VERSION 5.8 ;
BUSBITCHARS "[]" ;
DIVIDERCHAR "/" ;
UNITS
    DATABASE MICRONS 1000 ;
END UNITS

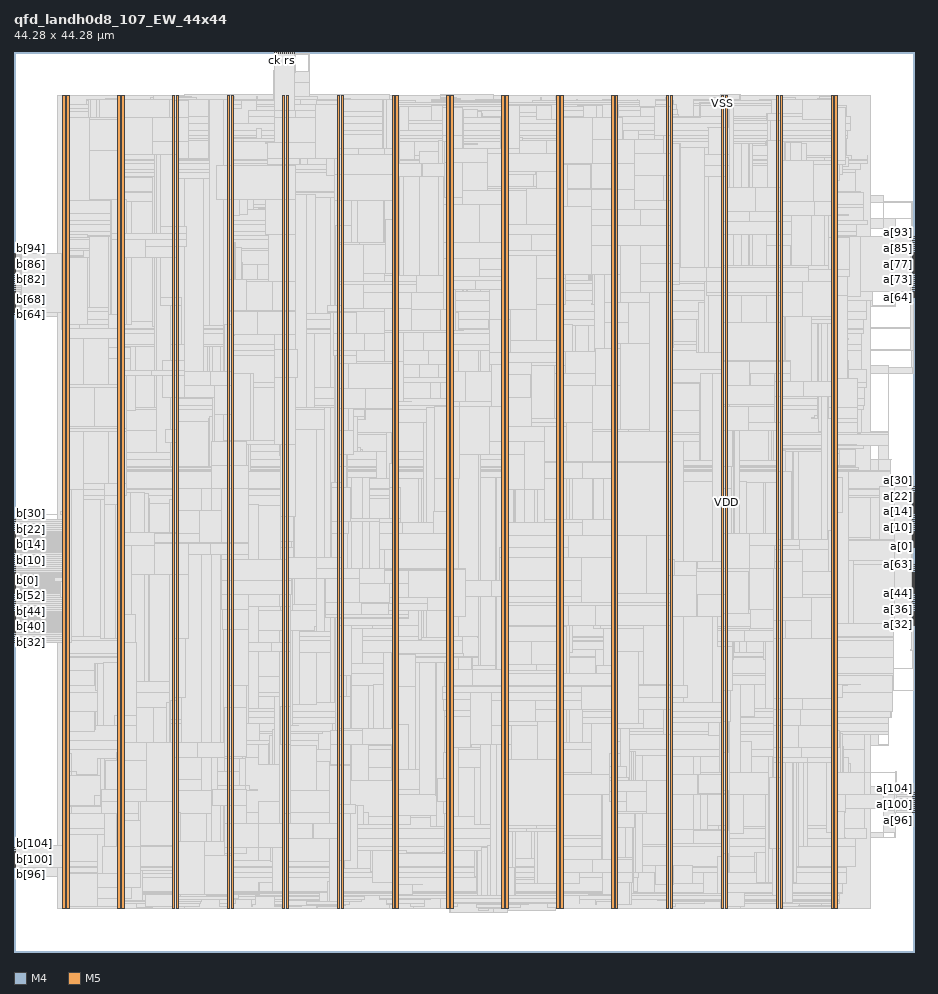
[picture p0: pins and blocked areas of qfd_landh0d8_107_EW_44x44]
MACRO qfd_landh0d8_107_EW_44x44
  FOREIGN qfd_landh0d8_107_EW_44x44 0 0 ;
  CLASS BLOCK ;
  SIZE 44.28 BY 44.28 ;
  PIN a[0]
    DIRECTION INPUT ;
    USE SIGNAL ;
    PORT
      LAYER M4 ;
        RECT  44.196 19.92 44.28 19.944 ;
    END
  END a[0]
  PIN a[100]
    DIRECTION INPUT ;
    USE SIGNAL ;
    PORT
      LAYER M4 ;
        RECT  44.196 7.248 44.28 7.272 ;
    END
  END a[100]
  PIN a[101]
    DIRECTION INPUT ;
    USE SIGNAL ;
    PORT
      LAYER M4 ;
        RECT  44.196 7.344 44.28 7.368 ;
    END
  END a[101]
  PIN a[102]
    DIRECTION INPUT ;
    USE SIGNAL ;
    PORT
      LAYER M4 ;
        RECT  44.196 7.44 44.28 7.464 ;
    END
  END a[102]
  PIN a[103]
    DIRECTION INPUT ;
    USE SIGNAL ;
    PORT
      LAYER M4 ;
        RECT  44.196 7.536 44.28 7.56 ;
    END
  END a[103]
  PIN a[104]
    DIRECTION INPUT ;
    USE SIGNAL ;
    PORT
      LAYER M4 ;
        RECT  44.196 7.632 44.28 7.656 ;
    END
  END a[104]
  PIN a[105]
    DIRECTION INPUT ;
    USE SIGNAL ;
    PORT
      LAYER M4 ;
        RECT  44.196 7.728 44.28 7.752 ;
    END
  END a[105]
  PIN a[106]
    DIRECTION INPUT ;
    USE SIGNAL ;
    PORT
      LAYER M4 ;
        RECT  44.196 7.824 44.28 7.848 ;
    END
  END a[106]
  PIN a[10]
    DIRECTION INPUT ;
    USE SIGNAL ;
    PORT
      LAYER M4 ;
        RECT  44.196 20.88 44.28 20.904 ;
    END
  END a[10]
  PIN a[11]
    DIRECTION INPUT ;
    USE SIGNAL ;
    PORT
      LAYER M4 ;
        RECT  44.196 20.976 44.28 21 ;
    END
  END a[11]
  PIN a[12]
    DIRECTION INPUT ;
    USE SIGNAL ;
    PORT
      LAYER M4 ;
        RECT  44.196 21.072 44.28 21.096 ;
    END
  END a[12]
  PIN a[13]
    DIRECTION INPUT ;
    USE SIGNAL ;
    PORT
      LAYER M4 ;
        RECT  44.196 21.168 44.28 21.192 ;
    END
  END a[13]
  PIN a[14]
    DIRECTION INPUT ;
    USE SIGNAL ;
    PORT
      LAYER M4 ;
        RECT  44.196 21.264 44.28 21.288 ;
    END
  END a[14]
  PIN a[15]
    DIRECTION INPUT ;
    USE SIGNAL ;
    PORT
      LAYER M4 ;
        RECT  44.196 21.36 44.28 21.384 ;
    END
  END a[15]
  PIN a[16]
    DIRECTION INPUT ;
    USE SIGNAL ;
    PORT
      LAYER M4 ;
        RECT  44.196 21.456 44.28 21.48 ;
    END
  END a[16]
  PIN a[17]
    DIRECTION INPUT ;
    USE SIGNAL ;
    PORT
      LAYER M4 ;
        RECT  44.196 21.552 44.28 21.576 ;
    END
  END a[17]
  PIN a[18]
    DIRECTION INPUT ;
    USE SIGNAL ;
    PORT
      LAYER M4 ;
        RECT  44.196 21.648 44.28 21.672 ;
    END
  END a[18]
  PIN a[19]
    DIRECTION INPUT ;
    USE SIGNAL ;
    PORT
      LAYER M4 ;
        RECT  44.196 21.744 44.28 21.768 ;
    END
  END a[19]
  PIN a[1]
    DIRECTION INPUT ;
    USE SIGNAL ;
    PORT
      LAYER M4 ;
        RECT  44.196 20.016 44.28 20.04 ;
    END
  END a[1]
  PIN a[20]
    DIRECTION INPUT ;
    USE SIGNAL ;
    PORT
      LAYER M4 ;
        RECT  44.196 21.84 44.28 21.864 ;
    END
  END a[20]
  PIN a[21]
    DIRECTION INPUT ;
    USE SIGNAL ;
    PORT
      LAYER M4 ;
        RECT  44.196 21.936 44.28 21.96 ;
    END
  END a[21]
  PIN a[22]
    DIRECTION INPUT ;
    USE SIGNAL ;
    PORT
      LAYER M4 ;
        RECT  44.196 22.032 44.28 22.056 ;
    END
  END a[22]
  PIN a[23]
    DIRECTION INPUT ;
    USE SIGNAL ;
    PORT
      LAYER M4 ;
        RECT  44.196 22.128 44.28 22.152 ;
    END
  END a[23]
  PIN a[24]
    DIRECTION INPUT ;
    USE SIGNAL ;
    PORT
      LAYER M4 ;
        RECT  44.196 22.224 44.28 22.248 ;
    END
  END a[24]
  PIN a[25]
    DIRECTION INPUT ;
    USE SIGNAL ;
    PORT
      LAYER M4 ;
        RECT  44.196 22.32 44.28 22.344 ;
    END
  END a[25]
  PIN a[26]
    DIRECTION INPUT ;
    USE SIGNAL ;
    PORT
      LAYER M4 ;
        RECT  44.196 22.416 44.28 22.44 ;
    END
  END a[26]
  PIN a[27]
    DIRECTION INPUT ;
    USE SIGNAL ;
    PORT
      LAYER M4 ;
        RECT  44.196 22.512 44.28 22.536 ;
    END
  END a[27]
  PIN a[28]
    DIRECTION INPUT ;
    USE SIGNAL ;
    PORT
      LAYER M4 ;
        RECT  44.196 22.608 44.28 22.632 ;
    END
  END a[28]
  PIN a[29]
    DIRECTION INPUT ;
    USE SIGNAL ;
    PORT
      LAYER M4 ;
        RECT  44.196 22.704 44.28 22.728 ;
    END
  END a[29]
  PIN a[2]
    DIRECTION INPUT ;
    USE SIGNAL ;
    PORT
      LAYER M4 ;
        RECT  44.196 20.112 44.28 20.136 ;
    END
  END a[2]
  PIN a[30]
    DIRECTION INPUT ;
    USE SIGNAL ;
    PORT
      LAYER M4 ;
        RECT  44.196 22.8 44.28 22.824 ;
    END
  END a[30]
  PIN a[31]
    DIRECTION INPUT ;
    USE SIGNAL ;
    PORT
      LAYER M4 ;
        RECT  44.196 22.896 44.28 22.92 ;
    END
  END a[31]
  PIN a[32]
    DIRECTION INPUT ;
    USE SIGNAL ;
    PORT
      LAYER M4 ;
        RECT  44.196 16.08 44.28 16.104 ;
    END
  END a[32]
  PIN a[33]
    DIRECTION INPUT ;
    USE SIGNAL ;
    PORT
      LAYER M4 ;
        RECT  44.196 16.176 44.28 16.2 ;
    END
  END a[33]
  PIN a[34]
    DIRECTION INPUT ;
    USE SIGNAL ;
    PORT
      LAYER M4 ;
        RECT  44.196 16.272 44.28 16.296 ;
    END
  END a[34]
  PIN a[35]
    DIRECTION INPUT ;
    USE SIGNAL ;
    PORT
      LAYER M4 ;
        RECT  44.196 16.368 44.28 16.392 ;
    END
  END a[35]
  PIN a[36]
    DIRECTION INPUT ;
    USE SIGNAL ;
    PORT
      LAYER M4 ;
        RECT  44.196 16.464 44.28 16.488 ;
    END
  END a[36]
  PIN a[37]
    DIRECTION INPUT ;
    USE SIGNAL ;
    PORT
      LAYER M4 ;
        RECT  44.196 16.56 44.28 16.584 ;
    END
  END a[37]
  PIN a[38]
    DIRECTION INPUT ;
    USE SIGNAL ;
    PORT
      LAYER M4 ;
        RECT  44.196 16.656 44.28 16.68 ;
    END
  END a[38]
  PIN a[39]
    DIRECTION INPUT ;
    USE SIGNAL ;
    PORT
      LAYER M4 ;
        RECT  44.196 16.752 44.28 16.776 ;
    END
  END a[39]
  PIN a[3]
    DIRECTION INPUT ;
    USE SIGNAL ;
    PORT
      LAYER M4 ;
        RECT  44.196 20.208 44.28 20.232 ;
    END
  END a[3]
  PIN a[40]
    DIRECTION INPUT ;
    USE SIGNAL ;
    PORT
      LAYER M4 ;
        RECT  44.196 16.848 44.28 16.872 ;
    END
  END a[40]
  PIN a[41]
    DIRECTION INPUT ;
    USE SIGNAL ;
    PORT
      LAYER M4 ;
        RECT  44.196 16.944 44.28 16.968 ;
    END
  END a[41]
  PIN a[42]
    DIRECTION INPUT ;
    USE SIGNAL ;
    PORT
      LAYER M4 ;
        RECT  44.196 17.04 44.28 17.064 ;
    END
  END a[42]
  PIN a[43]
    DIRECTION INPUT ;
    USE SIGNAL ;
    PORT
      LAYER M4 ;
        RECT  44.196 17.136 44.28 17.16 ;
    END
  END a[43]
  PIN a[44]
    DIRECTION INPUT ;
    USE SIGNAL ;
    PORT
      LAYER M4 ;
        RECT  44.196 17.232 44.28 17.256 ;
    END
  END a[44]
  PIN a[45]
    DIRECTION INPUT ;
    USE SIGNAL ;
    PORT
      LAYER M4 ;
        RECT  44.196 17.328 44.28 17.352 ;
    END
  END a[45]
  PIN a[46]
    DIRECTION INPUT ;
    USE SIGNAL ;
    PORT
      LAYER M4 ;
        RECT  44.196 17.424 44.28 17.448 ;
    END
  END a[46]
  PIN a[47]
    DIRECTION INPUT ;
    USE SIGNAL ;
    PORT
      LAYER M4 ;
        RECT  44.196 17.52 44.28 17.544 ;
    END
  END a[47]
  PIN a[48]
    DIRECTION INPUT ;
    USE SIGNAL ;
    PORT
      LAYER M4 ;
        RECT  44.196 17.616 44.28 17.64 ;
    END
  END a[48]
  PIN a[49]
    DIRECTION INPUT ;
    USE SIGNAL ;
    PORT
      LAYER M4 ;
        RECT  44.196 17.712 44.28 17.736 ;
    END
  END a[49]
  PIN a[4]
    DIRECTION INPUT ;
    USE SIGNAL ;
    PORT
      LAYER M4 ;
        RECT  44.196 20.304 44.28 20.328 ;
    END
  END a[4]
  PIN a[50]
    DIRECTION INPUT ;
    USE SIGNAL ;
    PORT
      LAYER M4 ;
        RECT  44.196 17.808 44.28 17.832 ;
    END
  END a[50]
  PIN a[51]
    DIRECTION INPUT ;
    USE SIGNAL ;
    PORT
      LAYER M4 ;
        RECT  44.196 17.904 44.28 17.928 ;
    END
  END a[51]
  PIN a[52]
    DIRECTION INPUT ;
    USE SIGNAL ;
    PORT
      LAYER M4 ;
        RECT  44.196 18 44.28 18.024 ;
    END
  END a[52]
  PIN a[53]
    DIRECTION INPUT ;
    USE SIGNAL ;
    PORT
      LAYER M4 ;
        RECT  44.196 18.096 44.28 18.12 ;
    END
  END a[53]
  PIN a[54]
    DIRECTION INPUT ;
    USE SIGNAL ;
    PORT
      LAYER M4 ;
        RECT  44.196 18.192 44.28 18.216 ;
    END
  END a[54]
  PIN a[55]
    DIRECTION INPUT ;
    USE SIGNAL ;
    PORT
      LAYER M4 ;
        RECT  44.196 18.288 44.28 18.312 ;
    END
  END a[55]
  PIN a[56]
    DIRECTION INPUT ;
    USE SIGNAL ;
    PORT
      LAYER M4 ;
        RECT  44.196 18.384 44.28 18.408 ;
    END
  END a[56]
  PIN a[57]
    DIRECTION INPUT ;
    USE SIGNAL ;
    PORT
      LAYER M4 ;
        RECT  44.196 18.48 44.28 18.504 ;
    END
  END a[57]
  PIN a[58]
    DIRECTION INPUT ;
    USE SIGNAL ;
    PORT
      LAYER M4 ;
        RECT  44.196 18.576 44.28 18.6 ;
    END
  END a[58]
  PIN a[59]
    DIRECTION INPUT ;
    USE SIGNAL ;
    PORT
      LAYER M4 ;
        RECT  44.196 18.672 44.28 18.696 ;
    END
  END a[59]
  PIN a[5]
    DIRECTION INPUT ;
    USE SIGNAL ;
    PORT
      LAYER M4 ;
        RECT  44.196 20.4 44.28 20.424 ;
    END
  END a[5]
  PIN a[60]
    DIRECTION INPUT ;
    USE SIGNAL ;
    PORT
      LAYER M4 ;
        RECT  44.196 18.768 44.28 18.792 ;
    END
  END a[60]
  PIN a[61]
    DIRECTION INPUT ;
    USE SIGNAL ;
    PORT
      LAYER M4 ;
        RECT  44.196 18.864 44.28 18.888 ;
    END
  END a[61]
  PIN a[62]
    DIRECTION INPUT ;
    USE SIGNAL ;
    PORT
      LAYER M4 ;
        RECT  44.196 18.96 44.28 18.984 ;
    END
  END a[62]
  PIN a[63]
    DIRECTION INPUT ;
    USE SIGNAL ;
    PORT
      LAYER M4 ;
        RECT  44.196 19.056 44.28 19.08 ;
    END
  END a[63]
  PIN a[64]
    DIRECTION INPUT ;
    USE SIGNAL ;
    PORT
      LAYER M4 ;
        RECT  44.196 32.208 44.28 32.232 ;
    END
  END a[64]
  PIN a[65]
    DIRECTION INPUT ;
    USE SIGNAL ;
    PORT
      LAYER M4 ;
        RECT  44.196 32.304 44.28 32.328 ;
    END
  END a[65]
  PIN a[66]
    DIRECTION INPUT ;
    USE SIGNAL ;
    PORT
      LAYER M4 ;
        RECT  44.196 32.4 44.28 32.424 ;
    END
  END a[66]
  PIN a[67]
    DIRECTION INPUT ;
    USE SIGNAL ;
    PORT
      LAYER M4 ;
        RECT  44.196 32.496 44.28 32.52 ;
    END
  END a[67]
  PIN a[68]
    DIRECTION INPUT ;
    USE SIGNAL ;
    PORT
      LAYER M4 ;
        RECT  44.196 32.592 44.28 32.616 ;
    END
  END a[68]
  PIN a[69]
    DIRECTION INPUT ;
    USE SIGNAL ;
    PORT
      LAYER M4 ;
        RECT  44.196 32.688 44.28 32.712 ;
    END
  END a[69]
  PIN a[6]
    DIRECTION INPUT ;
    USE SIGNAL ;
    PORT
      LAYER M4 ;
        RECT  44.196 20.496 44.28 20.52 ;
    END
  END a[6]
  PIN a[70]
    DIRECTION INPUT ;
    USE SIGNAL ;
    PORT
      LAYER M4 ;
        RECT  44.196 32.784 44.28 32.808 ;
    END
  END a[70]
  PIN a[71]
    DIRECTION INPUT ;
    USE SIGNAL ;
    PORT
      LAYER M4 ;
        RECT  44.196 32.88 44.28 32.904 ;
    END
  END a[71]
  PIN a[72]
    DIRECTION INPUT ;
    USE SIGNAL ;
    PORT
      LAYER M4 ;
        RECT  44.196 32.976 44.28 33 ;
    END
  END a[72]
  PIN a[73]
    DIRECTION INPUT ;
    USE SIGNAL ;
    PORT
      LAYER M4 ;
        RECT  44.196 33.072 44.28 33.096 ;
    END
  END a[73]
  PIN a[74]
    DIRECTION INPUT ;
    USE SIGNAL ;
    PORT
      LAYER M4 ;
        RECT  44.196 33.168 44.28 33.192 ;
    END
  END a[74]
  PIN a[75]
    DIRECTION INPUT ;
    USE SIGNAL ;
    PORT
      LAYER M4 ;
        RECT  44.196 33.264 44.28 33.288 ;
    END
  END a[75]
  PIN a[76]
    DIRECTION INPUT ;
    USE SIGNAL ;
    PORT
      LAYER M4 ;
        RECT  44.196 33.36 44.28 33.384 ;
    END
  END a[76]
  PIN a[77]
    DIRECTION INPUT ;
    USE SIGNAL ;
    PORT
      LAYER M4 ;
        RECT  44.196 33.456 44.28 33.48 ;
    END
  END a[77]
  PIN a[78]
    DIRECTION INPUT ;
    USE SIGNAL ;
    PORT
      LAYER M4 ;
        RECT  44.196 33.552 44.28 33.576 ;
    END
  END a[78]
  PIN a[79]
    DIRECTION INPUT ;
    USE SIGNAL ;
    PORT
      LAYER M4 ;
        RECT  44.196 33.648 44.28 33.672 ;
    END
  END a[79]
  PIN a[7]
    DIRECTION INPUT ;
    USE SIGNAL ;
    PORT
      LAYER M4 ;
        RECT  44.196 20.592 44.28 20.616 ;
    END
  END a[7]
  PIN a[80]
    DIRECTION INPUT ;
    USE SIGNAL ;
    PORT
      LAYER M4 ;
        RECT  44.196 33.744 44.28 33.768 ;
    END
  END a[80]
  PIN a[81]
    DIRECTION INPUT ;
    USE SIGNAL ;
    PORT
      LAYER M4 ;
        RECT  44.196 33.84 44.28 33.864 ;
    END
  END a[81]
  PIN a[82]
    DIRECTION INPUT ;
    USE SIGNAL ;
    PORT
      LAYER M4 ;
        RECT  44.196 33.936 44.28 33.96 ;
    END
  END a[82]
  PIN a[83]
    DIRECTION INPUT ;
    USE SIGNAL ;
    PORT
      LAYER M4 ;
        RECT  44.196 34.032 44.28 34.056 ;
    END
  END a[83]
  PIN a[84]
    DIRECTION INPUT ;
    USE SIGNAL ;
    PORT
      LAYER M4 ;
        RECT  44.196 34.128 44.28 34.152 ;
    END
  END a[84]
  PIN a[85]
    DIRECTION INPUT ;
    USE SIGNAL ;
    PORT
      LAYER M4 ;
        RECT  44.196 34.224 44.28 34.248 ;
    END
  END a[85]
  PIN a[86]
    DIRECTION INPUT ;
    USE SIGNAL ;
    PORT
      LAYER M4 ;
        RECT  44.196 34.32 44.28 34.344 ;
    END
  END a[86]
  PIN a[87]
    DIRECTION INPUT ;
    USE SIGNAL ;
    PORT
      LAYER M4 ;
        RECT  44.196 34.416 44.28 34.44 ;
    END
  END a[87]
  PIN a[88]
    DIRECTION INPUT ;
    USE SIGNAL ;
    PORT
      LAYER M4 ;
        RECT  44.196 34.512 44.28 34.536 ;
    END
  END a[88]
  PIN a[89]
    DIRECTION INPUT ;
    USE SIGNAL ;
    PORT
      LAYER M4 ;
        RECT  44.196 34.608 44.28 34.632 ;
    END
  END a[89]
  PIN a[8]
    DIRECTION INPUT ;
    USE SIGNAL ;
    PORT
      LAYER M4 ;
        RECT  44.196 20.688 44.28 20.712 ;
    END
  END a[8]
  PIN a[90]
    DIRECTION INPUT ;
    USE SIGNAL ;
    PORT
      LAYER M4 ;
        RECT  44.196 34.704 44.28 34.728 ;
    END
  END a[90]
  PIN a[91]
    DIRECTION INPUT ;
    USE SIGNAL ;
    PORT
      LAYER M4 ;
        RECT  44.196 34.8 44.28 34.824 ;
    END
  END a[91]
  PIN a[92]
    DIRECTION INPUT ;
    USE SIGNAL ;
    PORT
      LAYER M4 ;
        RECT  44.196 34.896 44.28 34.92 ;
    END
  END a[92]
  PIN a[93]
    DIRECTION INPUT ;
    USE SIGNAL ;
    PORT
      LAYER M4 ;
        RECT  44.196 34.992 44.28 35.016 ;
    END
  END a[93]
  PIN a[94]
    DIRECTION INPUT ;
    USE SIGNAL ;
    PORT
      LAYER M4 ;
        RECT  44.196 35.088 44.28 35.112 ;
    END
  END a[94]
  PIN a[95]
    DIRECTION INPUT ;
    USE SIGNAL ;
    PORT
      LAYER M4 ;
        RECT  44.196 35.184 44.28 35.208 ;
    END
  END a[95]
  PIN a[96]
    DIRECTION INPUT ;
    USE SIGNAL ;
    PORT
      LAYER M4 ;
        RECT  44.196 6.864 44.28 6.888 ;
    END
  END a[96]
  PIN a[97]
    DIRECTION INPUT ;
    USE SIGNAL ;
    PORT
      LAYER M4 ;
        RECT  44.196 6.96 44.28 6.984 ;
    END
  END a[97]
  PIN a[98]
    DIRECTION INPUT ;
    USE SIGNAL ;
    PORT
      LAYER M4 ;
        RECT  44.196 7.056 44.28 7.08 ;
    END
  END a[98]
  PIN a[99]
    DIRECTION INPUT ;
    USE SIGNAL ;
    PORT
      LAYER M4 ;
        RECT  44.196 7.152 44.28 7.176 ;
    END
  END a[99]
  PIN a[9]
    DIRECTION INPUT ;
    USE SIGNAL ;
    PORT
      LAYER M4 ;
        RECT  44.196 20.784 44.28 20.808 ;
    END
  END a[9]
  PIN b[0]
    DIRECTION OUTPUT ;
    USE SIGNAL ;
    PORT
      LAYER M4 ;
        RECT  0 18.288 0.084 18.312 ;
    END
  END b[0]
  PIN b[100]
    DIRECTION OUTPUT ;
    USE SIGNAL ;
    PORT
      LAYER M4 ;
        RECT  0 4.56 0.084 4.584 ;
    END
  END b[100]
  PIN b[101]
    DIRECTION OUTPUT ;
    USE SIGNAL ;
    PORT
      LAYER M4 ;
        RECT  0 4.656 0.084 4.68 ;
    END
  END b[101]
  PIN b[102]
    DIRECTION OUTPUT ;
    USE SIGNAL ;
    PORT
      LAYER M4 ;
        RECT  0 4.752 0.084 4.776 ;
    END
  END b[102]
  PIN b[103]
    DIRECTION OUTPUT ;
    USE SIGNAL ;
    PORT
      LAYER M4 ;
        RECT  0 4.848 0.084 4.872 ;
    END
  END b[103]
  PIN b[104]
    DIRECTION OUTPUT ;
    USE SIGNAL ;
    PORT
      LAYER M4 ;
        RECT  0 4.944 0.084 4.968 ;
    END
  END b[104]
  PIN b[105]
    DIRECTION OUTPUT ;
    USE SIGNAL ;
    PORT
      LAYER M4 ;
        RECT  0 5.04 0.084 5.064 ;
    END
  END b[105]
  PIN b[106]
    DIRECTION OUTPUT ;
    USE SIGNAL ;
    PORT
      LAYER M4 ;
        RECT  0 5.136 0.084 5.16 ;
    END
  END b[106]
  PIN b[10]
    DIRECTION OUTPUT ;
    USE SIGNAL ;
    PORT
      LAYER M4 ;
        RECT  0 19.248 0.084 19.272 ;
    END
  END b[10]
  PIN b[11]
    DIRECTION OUTPUT ;
    USE SIGNAL ;
    PORT
      LAYER M4 ;
        RECT  0 19.344 0.084 19.368 ;
    END
  END b[11]
  PIN b[12]
    DIRECTION OUTPUT ;
    USE SIGNAL ;
    PORT
      LAYER M4 ;
        RECT  0 19.44 0.084 19.464 ;
    END
  END b[12]
  PIN b[13]
    DIRECTION OUTPUT ;
    USE SIGNAL ;
    PORT
      LAYER M4 ;
        RECT  0 19.536 0.084 19.56 ;
    END
  END b[13]
  PIN b[14]
    DIRECTION OUTPUT ;
    USE SIGNAL ;
    PORT
      LAYER M4 ;
        RECT  0 19.632 0.084 19.656 ;
    END
  END b[14]
  PIN b[15]
    DIRECTION OUTPUT ;
    USE SIGNAL ;
    PORT
      LAYER M4 ;
        RECT  0 19.728 0.084 19.752 ;
    END
  END b[15]
  PIN b[16]
    DIRECTION OUTPUT ;
    USE SIGNAL ;
    PORT
      LAYER M4 ;
        RECT  0 19.824 0.084 19.848 ;
    END
  END b[16]
  PIN b[17]
    DIRECTION OUTPUT ;
    USE SIGNAL ;
    PORT
      LAYER M4 ;
        RECT  0 19.92 0.084 19.944 ;
    END
  END b[17]
  PIN b[18]
    DIRECTION OUTPUT ;
    USE SIGNAL ;
    PORT
      LAYER M4 ;
        RECT  0 20.016 0.084 20.04 ;
    END
  END b[18]
  PIN b[19]
    DIRECTION OUTPUT ;
    USE SIGNAL ;
    PORT
      LAYER M4 ;
        RECT  0 20.112 0.084 20.136 ;
    END
  END b[19]
  PIN b[1]
    DIRECTION OUTPUT ;
    USE SIGNAL ;
    PORT
      LAYER M4 ;
        RECT  0 18.384 0.084 18.408 ;
    END
  END b[1]
  PIN b[20]
    DIRECTION OUTPUT ;
    USE SIGNAL ;
    PORT
      LAYER M4 ;
        RECT  0 20.208 0.084 20.232 ;
    END
  END b[20]
  PIN b[21]
    DIRECTION OUTPUT ;
    USE SIGNAL ;
    PORT
      LAYER M4 ;
        RECT  0 20.304 0.084 20.328 ;
    END
  END b[21]
  PIN b[22]
    DIRECTION OUTPUT ;
    USE SIGNAL ;
    PORT
      LAYER M4 ;
        RECT  0 20.4 0.084 20.424 ;
    END
  END b[22]
  PIN b[23]
    DIRECTION OUTPUT ;
    USE SIGNAL ;
    PORT
      LAYER M4 ;
        RECT  0 20.496 0.084 20.52 ;
    END
  END b[23]
  PIN b[24]
    DIRECTION OUTPUT ;
    USE SIGNAL ;
    PORT
      LAYER M4 ;
        RECT  0 20.592 0.084 20.616 ;
    END
  END b[24]
  PIN b[25]
    DIRECTION OUTPUT ;
    USE SIGNAL ;
    PORT
      LAYER M4 ;
        RECT  0 20.688 0.084 20.712 ;
    END
  END b[25]
  PIN b[26]
    DIRECTION OUTPUT ;
    USE SIGNAL ;
    PORT
      LAYER M4 ;
        RECT  0 20.784 0.084 20.808 ;
    END
  END b[26]
  PIN b[27]
    DIRECTION OUTPUT ;
    USE SIGNAL ;
    PORT
      LAYER M4 ;
        RECT  0 20.88 0.084 20.904 ;
    END
  END b[27]
  PIN b[28]
    DIRECTION OUTPUT ;
    USE SIGNAL ;
    PORT
      LAYER M4 ;
        RECT  0 20.976 0.084 21 ;
    END
  END b[28]
  PIN b[29]
    DIRECTION OUTPUT ;
    USE SIGNAL ;
    PORT
      LAYER M4 ;
        RECT  0 21.072 0.084 21.096 ;
    END
  END b[29]
  PIN b[2]
    DIRECTION OUTPUT ;
    USE SIGNAL ;
    PORT
      LAYER M4 ;
        RECT  0 18.48 0.084 18.504 ;
    END
  END b[2]
  PIN b[30]
    DIRECTION OUTPUT ;
    USE SIGNAL ;
    PORT
      LAYER M4 ;
        RECT  0 21.168 0.084 21.192 ;
    END
  END b[30]
  PIN b[31]
    DIRECTION OUTPUT ;
    USE SIGNAL ;
    PORT
      LAYER M4 ;
        RECT  0 21.264 0.084 21.288 ;
    END
  END b[31]
  PIN b[32]
    DIRECTION OUTPUT ;
    USE SIGNAL ;
    PORT
      LAYER M4 ;
        RECT  0 15.216 0.084 15.24 ;
    END
  END b[32]
  PIN b[33]
    DIRECTION OUTPUT ;
    USE SIGNAL ;
    PORT
      LAYER M4 ;
        RECT  0 15.312 0.084 15.336 ;
    END
  END b[33]
  PIN b[34]
    DIRECTION OUTPUT ;
    USE SIGNAL ;
    PORT
      LAYER M4 ;
        RECT  0 15.408 0.084 15.432 ;
    END
  END b[34]
  PIN b[35]
    DIRECTION OUTPUT ;
    USE SIGNAL ;
    PORT
      LAYER M4 ;
        RECT  0 15.504 0.084 15.528 ;
    END
  END b[35]
  PIN b[36]
    DIRECTION OUTPUT ;
    USE SIGNAL ;
    PORT
      LAYER M4 ;
        RECT  0 15.6 0.084 15.624 ;
    END
  END b[36]
  PIN b[37]
    DIRECTION OUTPUT ;
    USE SIGNAL ;
    PORT
      LAYER M4 ;
        RECT  0 15.696 0.084 15.72 ;
    END
  END b[37]
  PIN b[38]
    DIRECTION OUTPUT ;
    USE SIGNAL ;
    PORT
      LAYER M4 ;
        RECT  0 15.792 0.084 15.816 ;
    END
  END b[38]
  PIN b[39]
    DIRECTION OUTPUT ;
    USE SIGNAL ;
    PORT
      LAYER M4 ;
        RECT  0 15.888 0.084 15.912 ;
    END
  END b[39]
  PIN b[3]
    DIRECTION OUTPUT ;
    USE SIGNAL ;
    PORT
      LAYER M4 ;
        RECT  0 18.576 0.084 18.6 ;
    END
  END b[3]
  PIN b[40]
    DIRECTION OUTPUT ;
    USE SIGNAL ;
    PORT
      LAYER M4 ;
        RECT  0 15.984 0.084 16.008 ;
    END
  END b[40]
  PIN b[41]
    DIRECTION OUTPUT ;
    USE SIGNAL ;
    PORT
      LAYER M4 ;
        RECT  0 16.08 0.084 16.104 ;
    END
  END b[41]
  PIN b[42]
    DIRECTION OUTPUT ;
    USE SIGNAL ;
    PORT
      LAYER M4 ;
        RECT  0 16.176 0.084 16.2 ;
    END
  END b[42]
  PIN b[43]
    DIRECTION OUTPUT ;
    USE SIGNAL ;
    PORT
      LAYER M4 ;
        RECT  0 16.272 0.084 16.296 ;
    END
  END b[43]
  PIN b[44]
    DIRECTION OUTPUT ;
    USE SIGNAL ;
    PORT
      LAYER M4 ;
        RECT  0 16.368 0.084 16.392 ;
    END
  END b[44]
  PIN b[45]
    DIRECTION OUTPUT ;
    USE SIGNAL ;
    PORT
      LAYER M4 ;
        RECT  0 16.464 0.084 16.488 ;
    END
  END b[45]
  PIN b[46]
    DIRECTION OUTPUT ;
    USE SIGNAL ;
    PORT
      LAYER M4 ;
        RECT  0 16.56 0.084 16.584 ;
    END
  END b[46]
  PIN b[47]
    DIRECTION OUTPUT ;
    USE SIGNAL ;
    PORT
      LAYER M4 ;
        RECT  0 16.656 0.084 16.68 ;
    END
  END b[47]
  PIN b[48]
    DIRECTION OUTPUT ;
    USE SIGNAL ;
    PORT
      LAYER M4 ;
        RECT  0 16.752 0.084 16.776 ;
    END
  END b[48]
  PIN b[49]
    DIRECTION OUTPUT ;
    USE SIGNAL ;
    PORT
      LAYER M4 ;
        RECT  0 16.848 0.084 16.872 ;
    END
  END b[49]
  PIN b[4]
    DIRECTION OUTPUT ;
    USE SIGNAL ;
    PORT
      LAYER M4 ;
        RECT  0 18.672 0.084 18.696 ;
    END
  END b[4]
  PIN b[50]
    DIRECTION OUTPUT ;
    USE SIGNAL ;
    PORT
      LAYER M4 ;
        RECT  0 16.944 0.084 16.968 ;
    END
  END b[50]
  PIN b[51]
    DIRECTION OUTPUT ;
    USE SIGNAL ;
    PORT
      LAYER M4 ;
        RECT  0 17.04 0.084 17.064 ;
    END
  END b[51]
  PIN b[52]
    DIRECTION OUTPUT ;
    USE SIGNAL ;
    PORT
      LAYER M4 ;
        RECT  0 17.136 0.084 17.16 ;
    END
  END b[52]
  PIN b[53]
    DIRECTION OUTPUT ;
    USE SIGNAL ;
    PORT
      LAYER M4 ;
        RECT  0 17.232 0.084 17.256 ;
    END
  END b[53]
  PIN b[54]
    DIRECTION OUTPUT ;
    USE SIGNAL ;
    PORT
      LAYER M4 ;
        RECT  0 17.328 0.084 17.352 ;
    END
  END b[54]
  PIN b[55]
    DIRECTION OUTPUT ;
    USE SIGNAL ;
    PORT
      LAYER M4 ;
        RECT  0 17.424 0.084 17.448 ;
    END
  END b[55]
  PIN b[56]
    DIRECTION OUTPUT ;
    USE SIGNAL ;
    PORT
      LAYER M4 ;
        RECT  0 17.52 0.084 17.544 ;
    END
  END b[56]
  PIN b[57]
    DIRECTION OUTPUT ;
    USE SIGNAL ;
    PORT
      LAYER M4 ;
        RECT  0 17.616 0.084 17.64 ;
    END
  END b[57]
  PIN b[58]
    DIRECTION OUTPUT ;
    USE SIGNAL ;
    PORT
      LAYER M4 ;
        RECT  0 17.712 0.084 17.736 ;
    END
  END b[58]
  PIN b[59]
    DIRECTION OUTPUT ;
    USE SIGNAL ;
    PORT
      LAYER M4 ;
        RECT  0 17.808 0.084 17.832 ;
    END
  END b[59]
  PIN b[5]
    DIRECTION OUTPUT ;
    USE SIGNAL ;
    PORT
      LAYER M4 ;
        RECT  0 18.768 0.084 18.792 ;
    END
  END b[5]
  PIN b[60]
    DIRECTION OUTPUT ;
    USE SIGNAL ;
    PORT
      LAYER M4 ;
        RECT  0 17.904 0.084 17.928 ;
    END
  END b[60]
  PIN b[61]
    DIRECTION OUTPUT ;
    USE SIGNAL ;
    PORT
      LAYER M4 ;
        RECT  0 18 0.084 18.024 ;
    END
  END b[61]
  PIN b[62]
    DIRECTION OUTPUT ;
    USE SIGNAL ;
    PORT
      LAYER M4 ;
        RECT  0 18.096 0.084 18.12 ;
    END
  END b[62]
  PIN b[63]
    DIRECTION OUTPUT ;
    USE SIGNAL ;
    PORT
      LAYER M4 ;
        RECT  0 18.192 0.084 18.216 ;
    END
  END b[63]
  PIN b[64]
    DIRECTION OUTPUT ;
    USE SIGNAL ;
    PORT
      LAYER M4 ;
        RECT  0 31.344 0.084 31.368 ;
    END
  END b[64]
  PIN b[65]
    DIRECTION OUTPUT ;
    USE SIGNAL ;
    PORT
      LAYER M4 ;
        RECT  0 31.44 0.084 31.464 ;
    END
  END b[65]
  PIN b[66]
    DIRECTION OUTPUT ;
    USE SIGNAL ;
    PORT
      LAYER M4 ;
        RECT  0 31.536 0.084 31.56 ;
    END
  END b[66]
  PIN b[67]
    DIRECTION OUTPUT ;
    USE SIGNAL ;
    PORT
      LAYER M4 ;
        RECT  0 31.632 0.084 31.656 ;
    END
  END b[67]
  PIN b[68]
    DIRECTION OUTPUT ;
    USE SIGNAL ;
    PORT
      LAYER M4 ;
        RECT  0 31.728 0.084 31.752 ;
    END
  END b[68]
  PIN b[69]
    DIRECTION OUTPUT ;
    USE SIGNAL ;
    PORT
      LAYER M4 ;
        RECT  0 31.824 0.084 31.848 ;
    END
  END b[69]
  PIN b[6]
    DIRECTION OUTPUT ;
    USE SIGNAL ;
    PORT
      LAYER M4 ;
        RECT  0 18.864 0.084 18.888 ;
    END
  END b[6]
  PIN b[70]
    DIRECTION OUTPUT ;
    USE SIGNAL ;
    PORT
      LAYER M4 ;
        RECT  0 31.92 0.084 31.944 ;
    END
  END b[70]
  PIN b[71]
    DIRECTION OUTPUT ;
    USE SIGNAL ;
    PORT
      LAYER M4 ;
        RECT  0 32.016 0.084 32.04 ;
    END
  END b[71]
  PIN b[72]
    DIRECTION OUTPUT ;
    USE SIGNAL ;
    PORT
      LAYER M4 ;
        RECT  0 32.112 0.084 32.136 ;
    END
  END b[72]
  PIN b[73]
    DIRECTION OUTPUT ;
    USE SIGNAL ;
    PORT
      LAYER M4 ;
        RECT  0 32.208 0.084 32.232 ;
    END
  END b[73]
  PIN b[74]
    DIRECTION OUTPUT ;
    USE SIGNAL ;
    PORT
      LAYER M4 ;
        RECT  0 32.304 0.084 32.328 ;
    END
  END b[74]
  PIN b[75]
    DIRECTION OUTPUT ;
    USE SIGNAL ;
    PORT
      LAYER M4 ;
        RECT  0 32.4 0.084 32.424 ;
    END
  END b[75]
  PIN b[76]
    DIRECTION OUTPUT ;
    USE SIGNAL ;
    PORT
      LAYER M4 ;
        RECT  0 32.496 0.084 32.52 ;
    END
  END b[76]
  PIN b[77]
    DIRECTION OUTPUT ;
    USE SIGNAL ;
    PORT
      LAYER M4 ;
        RECT  0 32.592 0.084 32.616 ;
    END
  END b[77]
  PIN b[78]
    DIRECTION OUTPUT ;
    USE SIGNAL ;
    PORT
      LAYER M4 ;
        RECT  0 32.688 0.084 32.712 ;
    END
  END b[78]
  PIN b[79]
    DIRECTION OUTPUT ;
    USE SIGNAL ;
    PORT
      LAYER M4 ;
        RECT  0 32.784 0.084 32.808 ;
    END
  END b[79]
  PIN b[7]
    DIRECTION OUTPUT ;
    USE SIGNAL ;
    PORT
      LAYER M4 ;
        RECT  0 18.96 0.084 18.984 ;
    END
  END b[7]
  PIN b[80]
    DIRECTION OUTPUT ;
    USE SIGNAL ;
    PORT
      LAYER M4 ;
        RECT  0 32.88 0.084 32.904 ;
    END
  END b[80]
  PIN b[81]
    DIRECTION OUTPUT ;
    USE SIGNAL ;
    PORT
      LAYER M4 ;
        RECT  0 32.976 0.084 33 ;
    END
  END b[81]
  PIN b[82]
    DIRECTION OUTPUT ;
    USE SIGNAL ;
    PORT
      LAYER M4 ;
        RECT  0 33.072 0.084 33.096 ;
    END
  END b[82]
  PIN b[83]
    DIRECTION OUTPUT ;
    USE SIGNAL ;
    PORT
      LAYER M4 ;
        RECT  0 33.168 0.084 33.192 ;
    END
  END b[83]
  PIN b[84]
    DIRECTION OUTPUT ;
    USE SIGNAL ;
    PORT
      LAYER M4 ;
        RECT  0 33.264 0.084 33.288 ;
    END
  END b[84]
  PIN b[85]
    DIRECTION OUTPUT ;
    USE SIGNAL ;
    PORT
      LAYER M4 ;
        RECT  0 33.36 0.084 33.384 ;
    END
  END b[85]
  PIN b[86]
    DIRECTION OUTPUT ;
    USE SIGNAL ;
    PORT
      LAYER M4 ;
        RECT  0 33.456 0.084 33.48 ;
    END
  END b[86]
  PIN b[87]
    DIRECTION OUTPUT ;
    USE SIGNAL ;
    PORT
      LAYER M4 ;
        RECT  0 33.552 0.084 33.576 ;
    END
  END b[87]
  PIN b[88]
    DIRECTION OUTPUT ;
    USE SIGNAL ;
    PORT
      LAYER M4 ;
        RECT  0 33.648 0.084 33.672 ;
    END
  END b[88]
  PIN b[89]
    DIRECTION OUTPUT ;
    USE SIGNAL ;
    PORT
      LAYER M4 ;
        RECT  0 33.744 0.084 33.768 ;
    END
  END b[89]
  PIN b[8]
    DIRECTION OUTPUT ;
    USE SIGNAL ;
    PORT
      LAYER M4 ;
        RECT  0 19.056 0.084 19.08 ;
    END
  END b[8]
  PIN b[90]
    DIRECTION OUTPUT ;
    USE SIGNAL ;
    PORT
      LAYER M4 ;
        RECT  0 33.84 0.084 33.864 ;
    END
  END b[90]
  PIN b[91]
    DIRECTION OUTPUT ;
    USE SIGNAL ;
    PORT
      LAYER M4 ;
        RECT  0 33.936 0.084 33.96 ;
    END
  END b[91]
  PIN b[92]
    DIRECTION OUTPUT ;
    USE SIGNAL ;
    PORT
      LAYER M4 ;
        RECT  0 34.032 0.084 34.056 ;
    END
  END b[92]
  PIN b[93]
    DIRECTION OUTPUT ;
    USE SIGNAL ;
    PORT
      LAYER M4 ;
        RECT  0 34.128 0.084 34.152 ;
    END
  END b[93]
  PIN b[94]
    DIRECTION OUTPUT ;
    USE SIGNAL ;
    PORT
      LAYER M4 ;
        RECT  0 34.224 0.084 34.248 ;
    END
  END b[94]
  PIN b[95]
    DIRECTION OUTPUT ;
    USE SIGNAL ;
    PORT
      LAYER M4 ;
        RECT  0 34.32 0.084 34.344 ;
    END
  END b[95]
  PIN b[96]
    DIRECTION OUTPUT ;
    USE SIGNAL ;
    PORT
      LAYER M4 ;
        RECT  0 4.176 0.084 4.2 ;
    END
  END b[96]
  PIN b[97]
    DIRECTION OUTPUT ;
    USE SIGNAL ;
    PORT
      LAYER M4 ;
        RECT  0 4.272 0.084 4.296 ;
    END
  END b[97]
  PIN b[98]
    DIRECTION OUTPUT ;
    USE SIGNAL ;
    PORT
      LAYER M4 ;
        RECT  0 4.368 0.084 4.392 ;
    END
  END b[98]
  PIN b[99]
    DIRECTION OUTPUT ;
    USE SIGNAL ;
    PORT
      LAYER M4 ;
        RECT  0 4.464 0.084 4.488 ;
    END
  END b[99]
  PIN b[9]
    DIRECTION OUTPUT ;
    USE SIGNAL ;
    PORT
      LAYER M4 ;
        RECT  0 19.152 0.084 19.176 ;
    END
  END b[9]
  PIN ck
    DIRECTION INPUT ;
    USE SIGNAL ;
    PORT
      LAYER M5 ;
        RECT  12.816 44.196 12.84 44.28 ;
    END
  END ck
  PIN ck_s
    DIRECTION INPUT ;
    USE SIGNAL ;
    PORT
      LAYER M5 ;
        RECT  12.912 44.196 12.936 44.28 ;
    END
  END ck_s
  PIN en
    DIRECTION INPUT ;
    USE SIGNAL ;
    PORT
      LAYER M5 ;
        RECT  13.008 44.196 13.032 44.28 ;
    END
  END en
  PIN fault
    DIRECTION OUTPUT ;
    USE SIGNAL ;
    PORT
      LAYER M5 ;
        RECT  13.104 44.196 13.128 44.28 ;
    END
  END fault
  PIN k0
    DIRECTION INPUT ;
    USE SIGNAL ;
    PORT
      LAYER M5 ;
        RECT  13.2 44.196 13.224 44.28 ;
    END
  END k0
  PIN k1
    DIRECTION INPUT ;
    USE SIGNAL ;
    PORT
      LAYER M5 ;
        RECT  13.296 44.196 13.32 44.28 ;
    END
  END k1
  PIN k2
    DIRECTION INPUT ;
    USE SIGNAL ;
    PORT
      LAYER M5 ;
        RECT  13.392 44.196 13.416 44.28 ;
    END
  END k2
  PIN k3
    DIRECTION INPUT ;
    USE SIGNAL ;
    PORT
      LAYER M5 ;
        RECT  13.488 44.196 13.512 44.28 ;
    END
  END k3
  PIN rs
    DIRECTION INPUT ;
    USE SIGNAL ;
    PORT
      LAYER M5 ;
        RECT  13.584 44.196 13.608 44.28 ;
    END
  END rs
  PIN tie_hi
    DIRECTION OUTPUT ;
    USE SIGNAL ;
    PORT
      LAYER M5 ;
        RECT  13.68 44.196 13.704 44.28 ;
    END
  END tie_hi
  PIN tie_lo
    DIRECTION OUTPUT ;
    USE SIGNAL ;
    PORT
      LAYER M5 ;
        RECT  13.776 44.196 13.8 44.28 ;
    END
  END tie_lo
  PIN VSS
    DIRECTION INOUT ;
    USE GROUND ;
    PORT
      LAYER M5 ;
        RECT  40.2 2.137 40.32 42.143 ;
        RECT  37.5 2.137 37.62 42.143 ;
        RECT  34.8 2.137 34.92 42.143 ;
        RECT  32.1 2.137 32.22 42.143 ;
        RECT  29.4 2.137 29.52 42.143 ;
        RECT  26.7 2.137 26.82 42.143 ;
        RECT  24 2.137 24.12 42.143 ;
        RECT  21.3 2.137 21.42 42.143 ;
        RECT  18.6 2.137 18.72 42.143 ;
        RECT  15.9 2.137 16.02 42.143 ;
        RECT  13.2 2.137 13.32 42.143 ;
        RECT  10.5 2.137 10.62 42.143 ;
        RECT  7.8 2.137 7.92 42.143 ;
        RECT  5.1 2.137 5.22 42.143 ;
        RECT  2.4 2.137 2.52 42.143 ;
    END
  END VSS
  PIN VDD
    DIRECTION INOUT ;
    USE POWER ;
    PORT
      LAYER M5 ;
        RECT  40.392 2.151 40.512 42.129 ;
        RECT  37.692 2.151 37.812 42.129 ;
        RECT  34.992 2.151 35.112 42.129 ;
        RECT  32.292 2.151 32.412 42.129 ;
        RECT  29.592 2.151 29.712 42.129 ;
        RECT  26.892 2.151 27.012 42.129 ;
        RECT  24.192 2.151 24.312 42.129 ;
        RECT  21.492 2.151 21.612 42.129 ;
        RECT  18.792 2.151 18.912 42.129 ;
        RECT  16.092 2.151 16.212 42.129 ;
        RECT  13.392 2.151 13.512 42.129 ;
        RECT  10.692 2.151 10.812 42.129 ;
        RECT  7.992 2.151 8.112 42.129 ;
        RECT  5.292 2.151 5.412 42.129 ;
        RECT  2.592 2.151 2.712 42.129 ;
    END
  END VDD
  # OT_OBS_CLOSED layer=M5 d_um=1.536 added=232
  OBS
    LAYER RVTN ;
     RECT  2.16 2.16 42.12 2.295 ;
     RECT  2.16 2.565 42.12 2.835 ;
     RECT  2.16 3.105 42.12 3.375 ;
     RECT  2.16 3.645 42.12 3.915 ;
     RECT  2.16 4.185 42.12 4.455 ;
     RECT  2.16 4.725 42.12 4.995 ;
     RECT  2.16 5.265 42.12 5.535 ;
     RECT  2.16 5.805 42.12 6.075 ;
     RECT  2.16 6.345 42.12 6.615 ;
     RECT  2.16 6.885 42.12 7.155 ;
     RECT  2.16 7.425 42.12 7.695 ;
     RECT  2.16 7.965 42.12 8.235 ;
     RECT  2.16 8.505 42.12 8.775 ;
     RECT  2.16 9.045 42.12 9.315 ;
     RECT  2.16 9.585 42.12 9.855 ;
     RECT  2.16 10.125 42.12 10.395 ;
     RECT  2.16 10.665 42.12 10.935 ;
     RECT  2.16 11.205 42.12 11.475 ;
     RECT  2.16 11.745 42.12 12.015 ;
     RECT  2.16 12.285 42.12 12.555 ;
     RECT  2.16 12.825 42.12 13.095 ;
     RECT  2.16 13.365 42.12 13.635 ;
     RECT  2.16 13.905 42.12 14.175 ;
     RECT  2.16 14.445 42.12 14.715 ;
     RECT  2.16 14.985 42.12 15.255 ;
     RECT  2.16 15.525 42.12 15.795 ;
     RECT  2.16 16.065 42.12 16.335 ;
     RECT  2.16 16.605 42.12 16.875 ;
     RECT  2.16 17.145 42.12 17.415 ;
     RECT  2.16 17.685 42.12 17.955 ;
     RECT  2.16 18.225 42.12 18.495 ;
     RECT  2.16 18.765 42.12 19.035 ;
     RECT  2.16 19.305 42.12 19.575 ;
     RECT  2.16 19.845 42.12 20.115 ;
     RECT  2.16 20.385 42.12 20.655 ;
     RECT  2.16 20.925 42.12 21.195 ;
     RECT  2.16 21.465 42.12 21.735 ;
     RECT  2.16 22.005 42.12 22.275 ;
     RECT  2.16 22.545 42.12 22.815 ;
     RECT  2.16 23.085 42.12 23.355 ;
     RECT  2.16 23.625 42.12 23.895 ;
     RECT  2.16 24.165 42.12 24.435 ;
     RECT  2.16 24.705 42.12 24.975 ;
     RECT  2.16 25.245 42.12 25.515 ;
     RECT  2.16 25.785 42.12 26.055 ;
     RECT  2.16 26.325 42.12 26.595 ;
     RECT  2.16 26.865 42.12 27.135 ;
     RECT  2.16 27.405 42.12 27.675 ;
     RECT  2.16 27.945 42.12 28.215 ;
     RECT  2.16 28.485 42.12 28.755 ;
     RECT  2.16 29.025 42.12 29.295 ;
     RECT  2.16 29.565 42.12 29.835 ;
     RECT  2.16 30.105 42.12 30.375 ;
     RECT  2.16 30.645 42.12 30.915 ;
     RECT  2.16 31.185 42.12 31.455 ;
     RECT  2.16 31.725 42.12 31.995 ;
     RECT  2.16 32.265 42.12 32.535 ;
     RECT  2.16 32.805 42.12 33.075 ;
     RECT  2.16 33.345 42.12 33.615 ;
     RECT  2.16 33.885 42.12 34.155 ;
     RECT  2.16 34.425 42.12 34.695 ;
     RECT  2.16 34.965 42.12 35.235 ;
     RECT  2.16 35.505 42.12 35.775 ;
     RECT  2.16 36.045 42.12 36.315 ;
     RECT  2.16 36.585 42.12 36.855 ;
     RECT  2.16 37.125 42.12 37.395 ;
     RECT  2.16 37.665 42.12 37.935 ;
     RECT  2.16 38.205 42.12 38.475 ;
     RECT  2.16 38.745 42.12 39.015 ;
     RECT  2.16 39.285 42.12 39.555 ;
     RECT  2.16 39.825 42.12 40.095 ;
     RECT  2.16 40.365 42.12 40.635 ;
     RECT  2.16 40.905 42.12 41.175 ;
     RECT  2.16 41.445 42.12 41.715 ;
     RECT  2.16 41.985 42.12 42.12 ;
    LAYER RVTP ;
     RECT  2.16 2.295 42.12 2.565 ;
     RECT  2.16 2.835 42.12 3.105 ;
     RECT  2.16 3.375 42.12 3.645 ;
     RECT  2.16 3.915 42.12 4.185 ;
     RECT  2.16 4.455 42.12 4.725 ;
     RECT  2.16 4.995 42.12 5.265 ;
     RECT  2.16 5.535 42.12 5.805 ;
     RECT  2.16 6.075 42.12 6.345 ;
     RECT  2.16 6.615 42.12 6.885 ;
     RECT  2.16 7.155 42.12 7.425 ;
     RECT  2.16 7.695 42.12 7.965 ;
     RECT  2.16 8.235 42.12 8.505 ;
     RECT  2.16 8.775 42.12 9.045 ;
     RECT  2.16 9.315 42.12 9.585 ;
     RECT  2.16 9.855 42.12 10.125 ;
     RECT  2.16 10.395 42.12 10.665 ;
     RECT  2.16 10.935 42.12 11.205 ;
     RECT  2.16 11.475 42.12 11.745 ;
     RECT  2.16 12.015 42.12 12.285 ;
     RECT  2.16 12.555 42.12 12.825 ;
     RECT  2.16 13.095 42.12 13.365 ;
     RECT  2.16 13.635 42.12 13.905 ;
     RECT  2.16 14.175 42.12 14.445 ;
     RECT  2.16 14.715 42.12 14.985 ;
     RECT  2.16 15.255 42.12 15.525 ;
     RECT  2.16 15.795 42.12 16.065 ;
     RECT  2.16 16.335 42.12 16.605 ;
     RECT  2.16 16.875 42.12 17.145 ;
     RECT  2.16 17.415 42.12 17.685 ;
     RECT  2.16 17.955 42.12 18.225 ;
     RECT  2.16 18.495 42.12 18.765 ;
     RECT  2.16 19.035 42.12 19.305 ;
     RECT  2.16 19.575 42.12 19.845 ;
     RECT  2.16 20.115 42.12 20.385 ;
     RECT  2.16 20.655 42.12 20.925 ;
     RECT  2.16 21.195 42.12 21.465 ;
     RECT  2.16 21.735 42.12 22.005 ;
     RECT  2.16 22.275 42.12 22.545 ;
     RECT  2.16 22.815 42.12 23.085 ;
     RECT  2.16 23.355 42.12 23.625 ;
     RECT  2.16 23.895 42.12 24.165 ;
     RECT  2.16 24.435 42.12 24.705 ;
     RECT  2.16 24.975 42.12 25.245 ;
     RECT  2.16 25.515 42.12 25.785 ;
     RECT  2.16 26.055 42.12 26.325 ;
     RECT  2.16 26.595 42.12 26.865 ;
     RECT  2.16 27.135 42.12 27.405 ;
     RECT  2.16 27.675 42.12 27.945 ;
     RECT  2.16 28.215 42.12 28.485 ;
     RECT  2.16 28.755 42.12 29.025 ;
     RECT  2.16 29.295 42.12 29.565 ;
     RECT  2.16 29.835 42.12 30.105 ;
     RECT  2.16 30.375 42.12 30.645 ;
     RECT  2.16 30.915 42.12 31.185 ;
     RECT  2.16 31.455 42.12 31.725 ;
     RECT  2.16 31.995 42.12 32.265 ;
     RECT  2.16 32.535 42.12 32.805 ;
     RECT  2.16 33.075 42.12 33.345 ;
     RECT  2.16 33.615 42.12 33.885 ;
     RECT  2.16 34.155 42.12 34.425 ;
     RECT  2.16 34.695 42.12 34.965 ;
     RECT  2.16 35.235 42.12 35.505 ;
     RECT  2.16 35.775 42.12 36.045 ;
     RECT  2.16 36.315 42.12 36.585 ;
     RECT  2.16 36.855 42.12 37.125 ;
     RECT  2.16 37.395 42.12 37.665 ;
     RECT  2.16 37.935 42.12 38.205 ;
     RECT  2.16 38.475 42.12 38.745 ;
     RECT  2.16 39.015 42.12 39.285 ;
     RECT  2.16 39.555 42.12 39.825 ;
     RECT  2.16 40.095 42.12 40.365 ;
     RECT  2.16 40.635 42.12 40.905 ;
     RECT  2.16 41.175 42.12 41.445 ;
     RECT  2.16 41.715 42.12 41.985 ;
    LAYER M1 ;
     RECT  2.16 2.151 42.12 42.129 ;
    LAYER M2 ;
     RECT  0.103 4.266 0.139 4.284 ;
     RECT  0.103 15.606 0.139 15.624 ;
     RECT  0.139 15.606 0.203 15.894 ;
     RECT  0.103 18.351 0.203 19.026 ;
     RECT  0.103 19.971 0.203 20.574 ;
     RECT  0.203 20.196 0.239 20.214 ;
     RECT  0.139 3.888 0.535 4.284 ;
     RECT  0.103 31.266 0.535 32.454 ;
     RECT  0.499 33.201 0.535 33.219 ;
     RECT  0.535 31.266 0.571 33.219 ;
     RECT  0.103 33.966 0.571 33.984 ;
     RECT  0.203 15.876 1.111 15.894 ;
     RECT  0.535 3.726 2.16 4.284 ;
     RECT  1.111 15.876 2.16 16.362 ;
     RECT  2.155 17.658 2.16 17.676 ;
     RECT  0.203 18.738 2.16 18.756 ;
     RECT  0.103 21.51 2.16 21.528 ;
     RECT  0.571 31.266 2.16 33.984 ;
     RECT  2.16 2.151 8.383 42.129 ;
     RECT  8.383 2.151 18.491 42.174 ;
     RECT  18.491 2.151 20.983 42.129 ;
     RECT  20.983 2.151 21.451 42.174 ;
     RECT  21.451 1.962 23.603 42.174 ;
     RECT  23.603 1.962 24.287 42.129 ;
     RECT  24.287 2.034 26.663 42.129 ;
     RECT  26.663 2.151 34.771 42.129 ;
     RECT  34.771 2.151 35.735 42.174 ;
     RECT  35.735 2.151 42.12 42.129 ;
     RECT  42.12 31.77 42.215 34.524 ;
     RECT  42.215 31.77 42.251 32.094 ;
     RECT  42.12 10.17 42.539 11.844 ;
     RECT  42.12 25.596 42.539 25.614 ;
     RECT  42.539 10.98 42.575 11.844 ;
     RECT  42.12 16.11 42.611 16.398 ;
     RECT  42.12 19.278 42.611 24.228 ;
     RECT  42.12 5.616 42.791 5.904 ;
     RECT  42.12 15.3 42.791 15.318 ;
     RECT  42.611 19.278 42.791 23.184 ;
     RECT  42.12 36.9 42.791 37.224 ;
     RECT  42.611 16.11 42.827 16.128 ;
     RECT  42.791 20.898 42.827 22.608 ;
     RECT  42.215 32.886 42.827 34.524 ;
     RECT  42.539 10.17 43.043 10.188 ;
     RECT  42.12 28.458 43.043 28.854 ;
     RECT  42.12 12.87 43.115 14.508 ;
     RECT  42.575 11.52 43.151 11.844 ;
     RECT  42.611 24.21 43.151 24.228 ;
     RECT  43.151 11.826 43.223 11.844 ;
     RECT  43.115 12.87 43.295 13.968 ;
     RECT  42.791 5.616 43.367 5.634 ;
     RECT  42.12 7.47 43.367 8.154 ;
     RECT  42.12 17.226 43.367 17.514 ;
     RECT  42.12 18.306 43.367 18.324 ;
     RECT  42.791 19.278 43.367 19.908 ;
     RECT  42.827 20.898 43.367 22.23 ;
     RECT  42.251 31.77 43.367 31.788 ;
     RECT  42.827 33.156 43.367 34.524 ;
     RECT  42.12 35.586 43.367 36.108 ;
     RECT  43.367 17.226 43.403 17.244 ;
     RECT  43.367 20.97 43.403 20.988 ;
     RECT  43.367 22.05 43.403 22.068 ;
     RECT  43.367 33.894 43.403 34.488 ;
     RECT  43.367 7.47 43.439 7.722 ;
     RECT  43.367 19.278 43.439 19.836 ;
     RECT  43.403 34.47 43.439 34.488 ;
     RECT  43.439 19.278 43.475 19.296 ;
     RECT  42.12 29.61 44.123 29.628 ;
     RECT  43.367 36.09 44.159 36.108 ;
     RECT  43.043 28.458 44.195 28.782 ;
     RECT  42.791 36.9 44.195 36.918 ;
     RECT  43.295 13.95 44.231 13.968 ;
     RECT  44.131 14.841 44.231 14.859 ;
     RECT  42.12 30.69 44.231 30.708 ;
     RECT  44.131 32.391 44.231 32.409 ;
     RECT  43.295 12.87 44.267 12.888 ;
     RECT  44.167 20.628 44.267 20.646 ;
     RECT  44.195 28.458 44.267 28.476 ;
    LAYER M3 ;
     RECT  23.328 2.029 23.346 2.065 ;
     RECT  21.456 1.957 21.474 2.143 ;
     RECT  22.86 2.065 23.346 2.143 ;
     RECT  24.264 1.957 24.282 2.143 ;
     RECT  26.64 2.029 26.658 2.143 ;
     RECT  7.815 2.143 7.905 2.191 ;
     RECT  13.215 2.143 13.305 2.191 ;
     RECT  22.86 2.143 24.282 2.191 ;
     RECT  26.64 2.143 26.805 2.191 ;
     RECT  7.815 2.191 7.974 2.227 ;
     RECT  13.176 2.191 13.446 2.227 ;
     RECT  19.656 2.191 19.674 2.227 ;
     RECT  21.315 2.143 21.474 2.227 ;
     RECT  37.515 2.143 37.605 2.227 ;
     RECT  7.815 2.227 9.126 2.251 ;
     RECT  40.215 2.143 40.305 2.251 ;
     RECT  4.14 2.227 4.158 2.263 ;
     RECT  5.115 2.143 5.205 2.263 ;
     RECT  10.515 2.143 10.605 2.263 ;
     RECT  14.904 2.191 14.922 2.263 ;
     RECT  15.915 2.143 16.005 2.263 ;
     RECT  19.512 2.227 19.674 2.263 ;
     RECT  29.415 2.143 29.505 2.263 ;
     RECT  32.115 2.143 32.205 2.263 ;
     RECT  12.816 2.227 14.13 2.299 ;
     RECT  14.904 2.263 16.005 2.299 ;
     RECT  11.7 2.263 11.718 2.335 ;
     RECT  12.816 2.299 16.326 2.335 ;
     RECT  18.615 2.143 18.705 2.335 ;
     RECT  22.752 2.191 24.93 2.335 ;
     RECT  29.415 2.263 29.574 2.335 ;
     RECT  34.815 2.143 34.905 2.335 ;
     RECT  29.415 2.335 30.114 2.347 ;
     RECT  4.14 2.263 5.205 2.371 ;
     RECT  6.012 2.191 6.822 2.371 ;
     RECT  7.632 2.251 9.126 2.371 ;
     RECT  10.116 2.263 10.605 2.371 ;
     RECT  18.324 2.335 18.774 2.371 ;
     RECT  19.512 2.263 20.178 2.371 ;
     RECT  21.315 2.227 21.798 2.371 ;
     RECT  22.752 2.335 25.326 2.371 ;
     RECT  26.244 2.191 26.805 2.371 ;
     RECT  32.115 2.263 32.526 2.371 ;
     RECT  34.815 2.335 34.974 2.371 ;
     RECT  35.928 2.251 35.946 2.371 ;
     RECT  37.515 2.227 38.646 2.371 ;
     RECT  39.708 2.251 40.305 2.371 ;
     RECT  2.415 2.143 2.505 2.413 ;
     RECT  21.315 2.371 26.805 2.413 ;
     RECT  4.14 2.371 9.198 2.461 ;
     RECT  12.816 2.335 16.506 2.461 ;
     RECT  32.115 2.371 33.966 2.461 ;
     RECT  34.815 2.371 40.626 2.461 ;
     RECT  28.62 2.335 28.638 2.497 ;
     RECT  29.415 2.347 30.366 2.497 ;
     RECT  32.115 2.461 40.626 2.533 ;
     RECT  4.14 2.461 9.234 2.569 ;
     RECT  10.116 2.371 10.89 2.569 ;
     RECT  12.816 2.461 17.118 2.569 ;
     RECT  4.14 2.569 10.89 2.605 ;
     RECT  11.7 2.335 11.862 2.605 ;
     RECT  18.324 2.371 20.178 2.605 ;
     RECT  27.828 2.371 27.846 2.605 ;
     RECT  28.62 2.497 30.402 2.605 ;
     RECT  31.644 2.533 40.626 2.605 ;
     RECT  18 2.605 20.502 2.641 ;
     RECT  21.315 2.413 26.997 2.641 ;
     RECT  4.14 2.605 11.862 2.731 ;
     RECT  12.816 2.569 17.226 2.731 ;
     RECT  4.14 2.731 17.226 2.767 ;
     RECT  18 2.641 26.997 2.767 ;
     RECT  27.828 2.605 40.626 2.767 ;
     RECT  3.996 2.767 17.226 2.803 ;
     RECT  18 2.767 40.626 2.803 ;
     RECT  3.996 2.803 40.626 2.875 ;
     RECT  3.996 2.875 40.77 2.903 ;
     RECT  2.415 2.413 2.697 2.971 ;
     RECT  3.996 2.903 30.69 2.971 ;
     RECT  31.5 2.903 40.77 3.379 ;
     RECT  2.415 2.971 30.69 3.676 ;
     RECT  0.54 3.721 0.558 3.883 ;
     RECT  2.415 3.676 30.726 3.931 ;
     RECT  31.5 3.379 40.95 3.931 ;
     RECT  2.415 3.931 40.95 4.171 ;
     RECT  2.304 4.171 40.95 4.225 ;
     RECT  0.144 3.883 0.558 4.261 ;
     RECT  0.108 4.261 0.558 4.397 ;
     RECT  2.304 4.225 41.418 5.189 ;
     RECT  0.108 4.397 0.126 5.261 ;
     RECT  2.415 5.189 41.418 5.575 ;
     RECT  43.344 5.611 43.362 5.881 ;
     RECT  2.415 5.575 41.922 6.071 ;
     RECT  42.768 5.881 43.362 6.989 ;
     RECT  43.344 6.989 43.362 7.435 ;
     RECT  43.344 7.435 43.398 7.465 ;
     RECT  43.344 7.465 43.434 7.853 ;
     RECT  43.344 7.853 43.398 8.159 ;
     RECT  43.38 8.159 43.398 8.861 ;
     RECT  2.415 6.071 41.85 9.959 ;
     RECT  2.415 9.959 14.994 10.427 ;
     RECT  15.915 9.959 41.85 10.705 ;
     RECT  43.02 10.165 43.038 10.705 ;
     RECT  12.06 10.427 14.994 10.741 ;
     RECT  12.06 10.741 15.174 10.843 ;
     RECT  15.915 10.705 43.038 10.843 ;
     RECT  2.415 10.427 11.07 11.227 ;
     RECT  12.06 10.843 43.038 11.227 ;
     RECT  2.415 11.227 43.038 11.515 ;
     RECT  2.415 11.515 43.146 11.551 ;
     RECT  2.376 11.551 43.146 11.821 ;
     RECT  2.376 11.821 43.218 11.849 ;
     RECT  2.415 11.849 43.218 12.755 ;
     RECT  23.652 12.755 43.218 13.603 ;
     RECT  2.415 12.755 22.878 13.711 ;
     RECT  23.652 13.603 43.29 13.711 ;
     RECT  44.244 12.865 44.262 13.945 ;
     RECT  2.415 13.711 43.29 14.513 ;
     RECT  2.415 14.513 38.034 14.549 ;
     RECT  2.415 14.549 22.122 14.675 ;
     RECT  44.208 13.945 44.262 14.836 ;
     RECT  22.86 14.549 38.034 15.295 ;
     RECT  2.415 14.675 22.05 15.307 ;
     RECT  22.86 15.295 38.07 15.331 ;
     RECT  38.88 14.513 43.29 15.331 ;
     RECT  22.86 15.331 43.29 15.493 ;
     RECT  2.304 15.307 22.05 15.499 ;
     RECT  22.788 15.493 43.29 15.499 ;
     RECT  0.144 15.403 0.162 15.601 ;
     RECT  0.108 15.601 0.198 15.869 ;
     RECT  0.108 15.869 0.162 15.917 ;
     RECT  44.136 14.836 44.262 16.013 ;
     RECT  44.136 16.013 44.19 16.109 ;
     RECT  1.116 16.339 1.134 16.781 ;
     RECT  2.304 15.499 43.29 16.799 ;
     RECT  4.392 16.799 43.29 17.221 ;
     RECT  44.136 16.109 44.154 17.357 ;
     RECT  2.304 16.799 3.618 17.581 ;
     RECT  4.392 17.221 43.398 17.581 ;
     RECT  2.304 17.581 43.398 17.611 ;
     RECT  2.16 17.611 43.398 17.681 ;
     RECT  2.304 17.681 43.398 17.837 ;
     RECT  0.144 15.917 0.162 18.091 ;
     RECT  0.108 18.091 0.162 18.139 ;
     RECT  2.304 17.837 43.362 18.329 ;
     RECT  0.108 18.139 0.198 18.733 ;
     RECT  0.108 18.733 0.558 19.181 ;
     RECT  2.376 18.329 43.218 19.243 ;
     RECT  2.304 19.243 43.218 19.273 ;
     RECT  0.108 19.181 0.198 20.011 ;
     RECT  0.108 20.011 0.342 20.141 ;
     RECT  0.108 20.141 0.234 20.219 ;
     RECT  2.304 19.273 43.47 20.237 ;
     RECT  2.304 20.237 43.398 20.285 ;
     RECT  44.172 20.587 44.19 20.623 ;
     RECT  44.172 20.623 44.262 20.651 ;
     RECT  44.244 20.651 44.262 20.669 ;
     RECT  0.108 20.219 0.198 20.971 ;
     RECT  2.415 20.285 43.398 20.993 ;
     RECT  0.108 20.971 0.342 21.101 ;
     RECT  2.415 20.993 43.362 21.259 ;
     RECT  0.108 21.101 0.126 21.533 ;
     RECT  2.376 21.259 43.362 21.541 ;
     RECT  2.304 21.541 43.362 21.659 ;
     RECT  22.392 21.659 43.362 22.045 ;
     RECT  2.415 21.659 21.654 22.459 ;
     RECT  22.392 22.045 43.398 22.459 ;
     RECT  2.415 22.459 43.398 22.733 ;
     RECT  2.415 22.733 43.146 22.781 ;
     RECT  2.415 22.781 30.006 23.665 ;
     RECT  30.888 22.781 43.146 23.665 ;
     RECT  2.415 23.665 43.146 23.693 ;
     RECT  2.415 23.693 41.562 23.729 ;
     RECT  2.415 23.729 41.526 23.819 ;
     RECT  2.415 23.819 41.418 23.891 ;
     RECT  30.6 23.891 41.418 23.927 ;
     RECT  42.516 23.693 43.146 24.233 ;
     RECT  2.415 23.891 29.697 24.241 ;
     RECT  30.6 23.927 40.59 24.503 ;
     RECT  2.376 24.241 29.697 24.629 ;
     RECT  2.415 24.629 29.697 24.637 ;
     RECT  30.6 24.503 35.91 24.637 ;
     RECT  36.72 24.503 40.59 24.709 ;
     RECT  41.4 23.927 41.418 24.709 ;
     RECT  36.72 24.709 41.418 24.781 ;
     RECT  36.72 24.781 41.778 24.907 ;
     RECT  42.516 24.233 43.038 24.907 ;
     RECT  2.415 24.637 35.91 25.447 ;
     RECT  36.72 24.907 43.038 25.447 ;
     RECT  2.415 25.447 43.038 25.583 ;
     RECT  42.516 25.583 43.038 25.619 ;
     RECT  2.415 25.583 41.706 26.671 ;
     RECT  2.415 26.671 41.778 26.905 ;
     RECT  2.415 26.905 41.85 27.239 ;
     RECT  21.315 27.239 41.85 27.751 ;
     RECT  21.315 27.751 41.922 28.013 ;
     RECT  2.415 27.239 20.502 28.021 ;
     RECT  21.315 28.013 29.754 28.021 ;
     RECT  30.636 28.013 41.922 28.679 ;
     RECT  44.244 28.453 44.262 28.759 ;
     RECT  43.02 25.619 43.038 28.859 ;
     RECT  2.415 28.021 29.754 29.371 ;
     RECT  2.415 29.371 29.934 29.605 ;
     RECT  30.744 28.679 41.706 29.605 ;
     RECT  44.172 28.759 44.262 29.605 ;
     RECT  2.415 29.605 41.706 29.911 ;
     RECT  2.412 29.911 41.706 30.451 ;
     RECT  2.412 30.451 41.778 30.619 ;
     RECT  2.34 30.619 41.778 30.677 ;
     RECT  2.415 30.677 41.778 31.117 ;
     RECT  0.108 31.261 0.126 31.339 ;
     RECT  2.415 31.117 41.922 31.531 ;
     RECT  0.108 31.339 0.342 31.729 ;
     RECT  0.108 31.729 0.558 31.949 ;
     RECT  44.1 29.605 44.262 31.949 ;
     RECT  2.268 31.531 41.922 32.071 ;
     RECT  44.1 31.949 44.226 32.414 ;
     RECT  44.1 32.414 44.154 32.429 ;
     RECT  2.268 32.071 42.246 32.525 ;
     RECT  0.108 31.949 0.234 32.717 ;
     RECT  44.136 32.429 44.154 32.717 ;
     RECT  0.18 32.717 0.234 32.765 ;
     RECT  0.216 32.765 0.234 32.875 ;
     RECT  1.116 32.539 1.134 32.875 ;
     RECT  2.415 32.525 42.246 32.875 ;
     RECT  43.344 31.765 43.362 32.875 ;
     RECT  0.216 32.875 1.134 33.224 ;
     RECT  0.216 33.224 0.594 33.377 ;
     RECT  2.415 32.875 43.362 33.413 ;
     RECT  42.732 33.413 43.362 33.449 ;
     RECT  0.216 33.377 0.522 33.547 ;
     RECT  44.172 33.355 44.19 33.643 ;
     RECT  2.415 33.413 41.67 33.677 ;
     RECT  2.415 33.677 3.402 33.739 ;
     RECT  42.768 33.449 43.362 33.889 ;
     RECT  0.108 33.547 0.522 33.989 ;
     RECT  0.504 33.989 0.522 34.061 ;
     RECT  2.376 33.739 3.402 34.219 ;
     RECT  2.304 34.219 3.402 34.259 ;
     RECT  42.768 33.889 43.398 34.465 ;
     RECT  44.136 33.643 44.19 34.465 ;
     RECT  2.415 34.259 3.402 34.501 ;
     RECT  4.176 33.677 41.67 34.501 ;
     RECT  2.415 34.501 41.67 34.619 ;
     RECT  42.768 34.465 44.19 34.637 ;
     RECT  2.415 34.619 41.526 35.033 ;
     RECT  2.415 35.033 41.454 35.275 ;
     RECT  2.376 35.275 41.454 35.429 ;
     RECT  42.768 34.637 43.362 35.609 ;
     RECT  2.415 35.429 41.454 35.815 ;
     RECT  2.415 35.815 41.994 35.969 ;
     RECT  44.136 34.637 44.19 36.113 ;
     RECT  2.415 35.969 41.778 36.625 ;
     RECT  2.376 36.625 41.778 36.779 ;
     RECT  44.172 36.113 44.19 36.923 ;
     RECT  42.768 35.609 42.786 37.229 ;
     RECT  2.415 36.779 41.778 37.355 ;
     RECT  2.415 37.355 41.634 37.427 ;
     RECT  2.415 37.427 41.418 38.371 ;
     RECT  2.376 38.371 41.418 38.515 ;
     RECT  2.376 38.515 41.634 38.785 ;
     RECT  2.376 38.785 41.994 38.939 ;
     RECT  2.415 38.939 41.994 38.975 ;
     RECT  19.728 38.975 41.202 39.209 ;
     RECT  41.976 38.975 41.994 39.209 ;
     RECT  2.415 38.975 18.99 39.901 ;
     RECT  19.728 39.209 40.95 39.901 ;
     RECT  2.415 39.901 40.95 40.027 ;
     RECT  2.415 40.027 41.022 40.171 ;
     RECT  2.376 40.171 41.022 40.405 ;
     RECT  2.376 40.405 41.166 40.739 ;
     RECT  11.556 40.739 41.166 41.099 ;
     RECT  31.572 41.099 32.67 41.207 ;
     RECT  2.376 40.739 10.797 41.369 ;
     RECT  11.556 41.099 30.834 41.405 ;
     RECT  31.572 41.207 32.634 41.441 ;
     RECT  2.415 41.369 10.797 41.485 ;
     RECT  11.916 41.405 30.834 41.597 ;
     RECT  33.444 41.099 40.95 41.639 ;
     RECT  2.415 41.485 11.178 41.675 ;
     RECT  31.572 41.441 32.598 41.675 ;
     RECT  11.916 41.597 30.762 41.711 ;
     RECT  33.444 41.639 40.497 41.747 ;
     RECT  17.784 41.711 30.762 41.783 ;
     RECT  17.892 41.783 24.297 41.819 ;
     RECT  2.415 41.675 2.697 41.867 ;
     RECT  20.556 41.819 24.297 41.867 ;
     RECT  39.492 41.747 40.497 41.867 ;
     RECT  3.564 41.675 11.178 41.909 ;
     RECT  11.916 41.711 16.938 41.909 ;
     RECT  17.892 41.819 19.746 41.909 ;
     RECT  20.556 41.867 24.105 41.909 ;
     RECT  25.488 41.783 30.762 41.909 ;
     RECT  31.572 41.675 32.454 41.909 ;
     RECT  33.444 41.747 38.682 41.909 ;
     RECT  39.492 41.867 40.374 41.909 ;
     RECT  3.564 41.909 5.238 41.933 ;
     RECT  4.392 41.933 5.238 41.945 ;
     RECT  10.515 41.909 10.998 41.945 ;
     RECT  12.78 41.909 16.938 41.945 ;
     RECT  17.892 41.909 18.774 41.945 ;
     RECT  20.556 41.909 21.978 41.945 ;
     RECT  22.716 41.909 24.105 41.945 ;
     RECT  27.684 41.909 27.702 41.945 ;
     RECT  28.944 41.909 29.505 41.945 ;
     RECT  30.672 41.909 30.69 41.945 ;
     RECT  31.572 41.909 32.205 41.945 ;
     RECT  33.444 41.909 35.73 41.945 ;
     RECT  36.684 41.909 38.61 41.945 ;
     RECT  39.492 41.909 40.305 41.945 ;
     RECT  11.916 41.909 11.97 41.954 ;
     RECT  4.5 41.945 5.205 41.981 ;
     RECT  15.915 41.945 16.542 41.981 ;
     RECT  20.988 41.945 21.978 41.981 ;
     RECT  39.528 41.945 40.305 41.981 ;
     RECT  32.076 41.945 32.205 42.017 ;
     RECT  34.272 41.945 34.905 42.017 ;
     RECT  37.515 41.945 38.466 42.017 ;
     RECT  6.696 41.909 6.858 42.053 ;
     RECT  7.815 41.909 8.982 42.053 ;
     RECT  20.988 41.981 21.762 42.053 ;
     RECT  25.92 41.909 25.938 42.053 ;
     RECT  6.84 42.053 6.858 42.089 ;
     RECT  7.815 42.053 8.73 42.089 ;
     RECT  10.515 41.945 10.854 42.089 ;
     RECT  11.952 41.954 11.97 42.089 ;
     RECT  12.78 41.945 14.922 42.089 ;
     RECT  39.636 41.981 40.305 42.089 ;
     RECT  2.415 41.867 2.505 42.137 ;
     RECT  5.115 41.981 5.205 42.137 ;
     RECT  7.815 42.089 8.406 42.137 ;
     RECT  10.515 42.089 10.605 42.137 ;
     RECT  15.915 41.981 16.005 42.137 ;
     RECT  18.468 41.945 18.705 42.137 ;
     RECT  20.988 42.053 21.405 42.137 ;
     RECT  23.58 41.945 24.105 42.137 ;
     RECT  26.715 41.909 26.805 42.137 ;
     RECT  29.415 41.945 29.505 42.137 ;
     RECT  32.115 42.017 32.205 42.137 ;
     RECT  34.776 42.017 34.905 42.137 ;
     RECT  37.515 42.017 37.605 42.137 ;
     RECT  40.215 42.089 40.305 42.137 ;
     RECT  8.388 42.137 8.406 42.179 ;
     RECT  18.468 42.137 18.486 42.179 ;
     RECT  20.988 42.137 21.006 42.179 ;
     RECT  23.58 42.137 23.598 42.179 ;
     RECT  34.776 42.137 34.794 42.179 ;
     RECT  35.712 41.945 35.73 42.179 ;
     RECT  12.78 42.089 14.526 42.797 ;
     RECT  13.716 42.797 14.526 43.325 ;
     RECT  12.78 42.797 12.798 43.373 ;
     RECT  13.716 43.325 13.734 44.141 ;
     RECT  14.508 43.325 14.526 44.189 ;
    LAYER M4 ;
     RECT  0.084 4.176 0.097 4.2 ;
     RECT  0.06 4.2 0.097 4.272 ;
     RECT  0.084 4.272 0.097 4.296 ;
     RECT  0.06 4.296 0.097 4.368 ;
     RECT  0.084 4.368 0.097 4.392 ;
     RECT  0.06 4.392 0.097 4.464 ;
     RECT  0.084 4.464 0.097 4.488 ;
     RECT  0.06 4.488 0.097 4.56 ;
     RECT  0.084 4.56 0.097 4.584 ;
     RECT  0.06 4.584 0.097 4.656 ;
     RECT  0.084 4.656 0.097 4.68 ;
     RECT  0.06 4.68 0.097 4.752 ;
     RECT  0.084 4.752 0.097 4.776 ;
     RECT  0.06 4.776 0.097 4.848 ;
     RECT  0.084 4.848 0.097 4.872 ;
     RECT  0.06 4.872 0.097 4.944 ;
     RECT  0.084 4.944 0.097 4.968 ;
     RECT  0.06 4.968 0.097 5.04 ;
     RECT  0.084 5.04 0.097 5.064 ;
     RECT  0.06 5.064 0.097 5.136 ;
     RECT  0.084 5.136 0.097 5.16 ;
     RECT  0.084 31.344 0.353 31.368 ;
     RECT  0.06 31.368 0.353 31.44 ;
     RECT  0.084 31.44 0.353 31.464 ;
     RECT  0.06 31.464 0.353 31.536 ;
     RECT  0.084 31.536 0.353 31.56 ;
     RECT  0.06 31.56 0.353 31.632 ;
     RECT  0.084 31.632 0.353 31.656 ;
     RECT  0.06 31.656 0.353 31.728 ;
     RECT  0.084 31.728 0.353 31.752 ;
     RECT  0.06 31.752 0.353 31.824 ;
     RECT  0.084 31.824 0.353 31.848 ;
     RECT  0.06 31.848 0.353 31.92 ;
     RECT  0.084 31.92 0.353 31.944 ;
     RECT  0.06 31.944 0.353 32.016 ;
     RECT  0.084 32.016 0.353 32.04 ;
     RECT  0.06 32.04 0.353 32.112 ;
     RECT  0.084 32.112 0.353 32.136 ;
     RECT  0.06 32.136 0.353 32.208 ;
     RECT  0.084 32.208 0.353 32.232 ;
     RECT  0.06 32.232 0.353 32.304 ;
     RECT  0.084 32.304 0.353 32.328 ;
     RECT  0.06 32.328 0.353 32.4 ;
     RECT  0.084 32.4 0.353 32.424 ;
     RECT  0.06 32.424 0.353 32.496 ;
     RECT  0.084 32.496 0.353 32.52 ;
     RECT  0.06 32.52 0.353 32.592 ;
     RECT  0.084 32.592 0.353 32.616 ;
     RECT  0.06 32.616 0.353 32.688 ;
     RECT  0.084 32.688 0.353 32.712 ;
     RECT  0.06 32.712 0.353 32.784 ;
     RECT  0.084 32.784 0.353 32.808 ;
     RECT  0.06 32.808 0.353 32.88 ;
     RECT  0.084 32.88 0.353 32.904 ;
     RECT  0.06 32.904 0.353 32.976 ;
     RECT  0.084 32.976 0.353 33 ;
     RECT  0.06 33 0.353 33.072 ;
     RECT  0.084 33.072 0.353 33.096 ;
     RECT  0.06 33.096 0.353 33.168 ;
     RECT  0.084 33.168 0.353 33.192 ;
     RECT  0.06 33.192 0.353 33.264 ;
     RECT  0.084 33.264 0.353 33.288 ;
     RECT  0.06 33.288 0.353 33.36 ;
     RECT  0.084 33.36 0.353 33.384 ;
     RECT  0.06 33.384 0.353 33.456 ;
     RECT  0.084 33.456 0.353 33.48 ;
     RECT  0.06 33.48 0.353 33.552 ;
     RECT  0.084 33.552 0.353 33.576 ;
     RECT  0.06 33.576 0.353 33.648 ;
     RECT  0.084 33.648 0.353 33.672 ;
     RECT  0.06 33.672 0.353 33.744 ;
     RECT  0.084 33.744 0.353 33.768 ;
     RECT  0.06 33.768 0.353 33.84 ;
     RECT  0.084 33.84 0.353 33.864 ;
     RECT  0.06 33.864 0.353 33.936 ;
     RECT  0.084 33.936 0.353 33.96 ;
     RECT  0.06 33.96 0.353 34.032 ;
     RECT  0.084 34.032 0.353 34.056 ;
     RECT  0.06 34.056 0.353 34.128 ;
     RECT  0.084 34.128 0.353 34.152 ;
     RECT  0.06 34.152 0.353 34.224 ;
     RECT  0.084 34.224 0.353 34.248 ;
     RECT  0.06 34.248 0.353 34.32 ;
     RECT  0.084 34.32 0.353 34.344 ;
     RECT  0.353 31.44 2.329 34.344 ;
     RECT  0.097 4.176 2.408 5.256 ;
     RECT  0.084 15.216 2.408 15.24 ;
     RECT  0.06 15.24 2.408 15.312 ;
     RECT  0.084 15.312 2.408 15.336 ;
     RECT  0.06 15.336 2.408 15.408 ;
     RECT  0.084 15.408 2.408 15.432 ;
     RECT  0.06 15.432 2.408 15.504 ;
     RECT  0.084 15.504 2.408 15.528 ;
     RECT  0.06 15.528 2.408 15.6 ;
     RECT  0.084 15.6 2.408 15.624 ;
     RECT  0.06 15.624 2.408 15.696 ;
     RECT  0.084 15.696 2.408 15.72 ;
     RECT  0.06 15.72 2.408 15.792 ;
     RECT  0.084 15.792 2.408 15.816 ;
     RECT  0.06 15.816 2.408 15.888 ;
     RECT  0.084 15.888 2.408 15.912 ;
     RECT  0.06 15.912 2.408 15.984 ;
     RECT  0.084 15.984 2.408 16.008 ;
     RECT  0.06 16.008 2.408 16.08 ;
     RECT  0.084 16.08 2.408 16.104 ;
     RECT  0.06 16.104 2.408 16.176 ;
     RECT  0.084 16.176 2.408 16.2 ;
     RECT  0.06 16.2 2.408 16.272 ;
     RECT  0.084 16.272 2.408 16.296 ;
     RECT  0.06 16.296 2.408 16.368 ;
     RECT  0.084 16.368 2.408 16.392 ;
     RECT  0.06 16.392 2.408 16.464 ;
     RECT  0.084 16.464 2.408 16.488 ;
     RECT  0.06 16.488 2.408 16.56 ;
     RECT  0.084 16.56 2.408 16.584 ;
     RECT  0.06 16.584 2.408 16.656 ;
     RECT  0.084 16.656 2.408 16.68 ;
     RECT  0.06 16.68 2.408 16.752 ;
     RECT  0.084 16.752 2.408 16.776 ;
     RECT  0.06 16.776 2.408 16.848 ;
     RECT  0.084 16.848 2.408 16.872 ;
     RECT  0.06 16.872 2.408 16.944 ;
     RECT  0.084 16.944 2.408 16.968 ;
     RECT  0.06 16.968 2.408 17.04 ;
     RECT  0.084 17.04 2.408 17.064 ;
     RECT  0.06 17.064 2.408 17.136 ;
     RECT  0.084 17.136 2.408 17.16 ;
     RECT  0.06 17.16 2.408 17.232 ;
     RECT  0.084 17.232 2.408 17.256 ;
     RECT  0.06 17.256 2.408 17.328 ;
     RECT  0.084 17.328 2.408 17.352 ;
     RECT  0.06 17.352 2.408 17.424 ;
     RECT  0.084 17.424 2.408 17.448 ;
     RECT  0.06 17.448 2.408 17.52 ;
     RECT  0.084 17.52 2.408 17.544 ;
     RECT  0.06 17.544 2.408 17.616 ;
     RECT  0.084 17.616 2.408 17.64 ;
     RECT  0.06 17.64 2.408 17.712 ;
     RECT  0.084 17.712 2.408 17.736 ;
     RECT  0.06 17.736 2.408 17.808 ;
     RECT  0.084 17.808 2.408 17.832 ;
     RECT  0.06 17.832 2.408 17.904 ;
     RECT  0.084 17.904 2.408 17.928 ;
     RECT  0.06 17.928 2.408 18 ;
     RECT  0.084 18 2.408 18.024 ;
     RECT  0.06 18.024 2.408 18.096 ;
     RECT  0.084 18.096 2.408 18.12 ;
     RECT  0.06 18.12 2.408 18.192 ;
     RECT  0.084 18.192 2.408 18.216 ;
     RECT  0.06 18.216 2.408 18.288 ;
     RECT  0.084 18.288 2.408 18.312 ;
     RECT  0.06 18.312 2.408 18.384 ;
     RECT  0.084 18.384 2.408 18.408 ;
     RECT  0.06 18.408 2.408 18.48 ;
     RECT  0.084 18.48 2.408 18.504 ;
     RECT  0.06 18.504 2.408 18.576 ;
     RECT  0.084 18.576 2.408 18.6 ;
     RECT  0.06 18.6 2.408 18.672 ;
     RECT  0.084 18.672 2.408 18.696 ;
     RECT  0.06 18.696 2.408 18.768 ;
     RECT  0.084 18.768 2.408 18.792 ;
     RECT  0.06 18.792 2.408 18.864 ;
     RECT  0.084 18.864 2.408 18.888 ;
     RECT  0.06 18.888 2.408 18.96 ;
     RECT  0.084 18.96 2.408 18.984 ;
     RECT  0.06 18.984 2.408 19.056 ;
     RECT  0.084 19.056 2.408 19.08 ;
     RECT  0.06 19.08 2.408 19.152 ;
     RECT  0.084 19.152 2.408 19.176 ;
     RECT  0.06 19.176 2.408 19.248 ;
     RECT  0.084 19.248 2.408 19.272 ;
     RECT  0.06 19.272 2.408 19.344 ;
     RECT  0.084 19.344 2.408 19.368 ;
     RECT  0.06 19.368 2.408 19.44 ;
     RECT  0.084 19.44 2.408 19.464 ;
     RECT  0.06 19.464 2.408 19.536 ;
     RECT  0.084 19.536 2.408 19.56 ;
     RECT  0.06 19.56 2.408 19.632 ;
     RECT  0.084 19.632 2.408 19.656 ;
     RECT  0.06 19.656 2.408 19.728 ;
     RECT  0.084 19.728 2.408 19.752 ;
     RECT  0.06 19.752 2.408 19.824 ;
     RECT  0.084 19.824 2.408 19.848 ;
     RECT  0.06 19.848 2.408 19.92 ;
     RECT  0.084 19.92 2.408 19.944 ;
     RECT  0.06 19.944 2.408 20.016 ;
     RECT  0.084 20.016 2.408 20.04 ;
     RECT  0.06 20.04 2.408 20.112 ;
     RECT  0.084 20.112 2.408 20.136 ;
     RECT  0.06 20.136 2.408 20.208 ;
     RECT  0.084 20.208 2.408 20.232 ;
     RECT  0.06 20.232 2.408 20.304 ;
     RECT  0.084 20.304 2.408 20.328 ;
     RECT  0.06 20.328 2.408 20.4 ;
     RECT  0.084 20.4 2.408 20.424 ;
     RECT  0.06 20.424 2.408 20.496 ;
     RECT  0.084 20.496 2.408 20.52 ;
     RECT  0.06 20.52 2.408 20.592 ;
     RECT  0.084 20.592 2.408 20.616 ;
     RECT  0.06 20.616 2.408 20.688 ;
     RECT  0.084 20.688 2.408 20.712 ;
     RECT  0.06 20.712 2.408 20.784 ;
     RECT  0.084 20.784 2.408 20.808 ;
     RECT  0.06 20.808 2.408 20.88 ;
     RECT  0.084 20.88 2.408 20.904 ;
     RECT  0.06 20.904 2.408 20.976 ;
     RECT  0.084 20.976 2.408 21 ;
     RECT  0.06 21 2.408 21.072 ;
     RECT  0.084 21.072 2.408 21.096 ;
     RECT  0.06 21.096 2.408 21.168 ;
     RECT  0.084 21.168 2.408 21.192 ;
     RECT  0.06 21.192 2.408 21.264 ;
     RECT  0.084 21.264 2.408 21.288 ;
     RECT  2.329 30.624 2.408 34.344 ;
     RECT  2.365 38.4 2.408 38.424 ;
     RECT  2.408 2.148 2.512 42.132 ;
     RECT  2.512 2.418 2.704 41.862 ;
     RECT  2.704 6.816 2.819 7.224 ;
     RECT  2.704 8.688 2.819 9.768 ;
     RECT  2.704 15.216 2.837 25.848 ;
     RECT  2.819 8.688 3.053 8.904 ;
     RECT  2.837 15.504 3.443 25.848 ;
     RECT  3.443 23.712 3.484 25.848 ;
     RECT  2.704 27.792 3.593 34.152 ;
     RECT  2.704 35.136 3.629 35.304 ;
     RECT  2.704 40.416 3.685 40.584 ;
     RECT  3.553 41.904 3.685 41.928 ;
     RECT  3.593 31.728 3.733 34.152 ;
     RECT  3.629 35.136 3.733 35.208 ;
     RECT  3.685 40.416 3.769 41.928 ;
     RECT  3.593 27.792 3.773 30.648 ;
     RECT  2.704 13.104 3.949 13.848 ;
     RECT  2.704 10.848 3.953 11.832 ;
     RECT  2.819 7.2 3.985 7.224 ;
     RECT  3.949 13.104 4.021 14.184 ;
     RECT  3.953 10.944 4.025 11.832 ;
     RECT  3.769 40.368 4.069 41.928 ;
     RECT  2.704 2.976 4.085 3 ;
     RECT  4.025 11.136 4.093 11.832 ;
     RECT  4.021 12.864 4.093 14.184 ;
     RECT  4.085 2.256 4.117 3 ;
     RECT  2.704 4.464 4.117 5.784 ;
     RECT  3.053 8.688 4.129 8.712 ;
     RECT  4.069 39.888 4.213 41.928 ;
     RECT  3.443 15.504 4.237 22.248 ;
     RECT  3.985 7.2 4.268 7.704 ;
     RECT  4.268 6.816 4.271 7.704 ;
     RECT  4.129 8.688 4.271 9.528 ;
     RECT  4.093 11.136 4.381 14.184 ;
     RECT  4.117 2.256 4.453 5.784 ;
     RECT  4.271 6.816 4.453 9.528 ;
     RECT  4.237 15.408 4.453 22.248 ;
     RECT  3.484 23.904 4.453 25.848 ;
     RECT  3.773 27.792 4.453 29.064 ;
     RECT  4.453 27.12 4.525 29.064 ;
     RECT  3.773 30.192 4.645 30.648 ;
     RECT  3.733 31.728 4.645 35.208 ;
     RECT  4.645 30.192 4.741 35.208 ;
     RECT  2.704 36.336 4.741 38.424 ;
     RECT  4.453 15.408 4.981 25.848 ;
     RECT  4.525 27.072 4.981 29.064 ;
     RECT  4.453 2.256 5.065 9.528 ;
     RECT  4.981 15.408 5.101 29.064 ;
     RECT  4.741 30.192 5.101 38.424 ;
     RECT  5.065 2.256 5.108 9.816 ;
     RECT  4.381 11.136 5.108 14.232 ;
     RECT  5.101 15.408 5.108 38.424 ;
     RECT  4.213 39.456 5.108 41.928 ;
     RECT  5.108 2.148 5.212 42.132 ;
     RECT  5.212 2.418 5.404 41.928 ;
     RECT  5.404 24.096 5.555 29.784 ;
     RECT  5.404 30.864 5.555 37.032 ;
     RECT  5.404 5.088 5.753 22.632 ;
     RECT  5.555 30.864 5.789 36.936 ;
     RECT  5.555 26.64 5.969 29.784 ;
     RECT  5.753 5.088 6.131 7.512 ;
     RECT  6.131 5.088 6.227 7.464 ;
     RECT  5.404 2.544 6.329 4.008 ;
     RECT  5.753 13.296 6.401 22.632 ;
     RECT  6.329 2.544 6.469 2.808 ;
     RECT  6.401 13.296 6.617 22.536 ;
     RECT  6.617 13.296 6.653 22.296 ;
     RECT  5.789 31.008 6.793 36.936 ;
     RECT  5.404 38.112 6.793 38.136 ;
     RECT  6.793 39.312 6.805 39.336 ;
     RECT  5.753 8.928 6.865 12.024 ;
     RECT  5.969 26.784 6.901 29.784 ;
     RECT  6.793 30.768 6.901 38.136 ;
     RECT  6.901 26.784 6.937 38.136 ;
     RECT  6.805 39.264 6.937 39.336 ;
     RECT  5.555 24.576 7.009 25.656 ;
     RECT  6.937 26.784 7.009 39.336 ;
     RECT  6.865 8.832 7.513 12.024 ;
     RECT  5.404 40.944 7.649 41.928 ;
     RECT  6.653 13.296 7.657 22.056 ;
     RECT  7.513 8.832 7.669 12.264 ;
     RECT  7.657 13.296 7.669 22.248 ;
     RECT  7.009 24.576 7.693 39.336 ;
     RECT  6.469 2.256 7.808 2.808 ;
     RECT  6.329 3.84 7.808 4.008 ;
     RECT  6.227 5.232 7.808 7.464 ;
     RECT  7.669 8.832 7.808 22.248 ;
     RECT  7.693 23.904 7.808 39.336 ;
     RECT  7.649 40.512 7.808 41.928 ;
     RECT  7.808 2.148 7.912 42.132 ;
     RECT  7.912 2.418 8.104 41.928 ;
     RECT  8.104 2.736 8.201 6.84 ;
     RECT  8.104 27.312 8.387 38.04 ;
     RECT  8.104 39.024 8.579 41.928 ;
     RECT  8.104 7.968 9.241 8.472 ;
     RECT  8.104 9.6 9.241 22.824 ;
     RECT  8.387 27.984 9.317 38.04 ;
     RECT  8.201 2.736 9.461 6.792 ;
     RECT  9.317 27.984 9.529 29.784 ;
     RECT  8.104 23.904 9.565 26.088 ;
     RECT  8.579 39.024 9.565 39.912 ;
     RECT  8.579 41.088 9.565 41.928 ;
     RECT  9.529 27.36 9.601 29.784 ;
     RECT  9.317 30.816 9.601 38.04 ;
     RECT  9.565 39.024 9.601 41.928 ;
     RECT  9.565 23.904 9.637 26.232 ;
     RECT  9.461 3.648 9.733 6.792 ;
     RECT  9.241 7.968 9.733 22.824 ;
     RECT  9.637 23.904 9.788 26.328 ;
     RECT  9.601 27.312 9.788 29.784 ;
     RECT  9.733 3.648 10.141 22.824 ;
     RECT  9.788 23.904 10.141 29.784 ;
     RECT  10.141 3.648 10.285 29.784 ;
     RECT  9.601 30.816 10.285 41.928 ;
     RECT  10.285 3.648 10.508 41.928 ;
     RECT  10.508 2.148 10.612 42.132 ;
     RECT  10.612 2.418 10.804 41.928 ;
     RECT  10.804 7.968 10.865 22.008 ;
     RECT  10.804 30.336 10.865 34.92 ;
     RECT  10.865 30.576 10.901 34.92 ;
     RECT  10.804 2.64 11.045 2.808 ;
     RECT  10.804 36.24 11.081 37.08 ;
     RECT  10.901 30.576 11.189 34.68 ;
     RECT  11.189 30.576 11.261 33.912 ;
     RECT  10.865 9.552 11.267 22.008 ;
     RECT  11.081 36.288 11.477 37.08 ;
     RECT  11.267 11.232 11.513 22.008 ;
     RECT  10.865 7.968 11.585 8.184 ;
     RECT  10.804 23.664 11.621 28.44 ;
     RECT  10.804 38.64 11.747 38.664 ;
     RECT  11.621 25.152 11.765 28.44 ;
     RECT  11.477 36.528 11.793 37.08 ;
     RECT  11.621 23.664 11.801 23.688 ;
     RECT  11.045 2.736 11.873 2.808 ;
     RECT  10.804 40.032 11.941 40.056 ;
     RECT  11.585 7.968 11.981 7.992 ;
     RECT  11.261 30.576 11.989 33.816 ;
     RECT  10.804 4.512 12.013 6.888 ;
     RECT  11.267 9.552 12.013 10.2 ;
     RECT  11.513 12 12.017 22.008 ;
     RECT  11.793 36.528 12.017 36.648 ;
     RECT  12.013 4.512 12.035 7.416 ;
     RECT  11.873 2.784 12.049 2.808 ;
     RECT  12.017 13.536 12.053 21.96 ;
     RECT  12.049 2.784 12.089 3.432 ;
     RECT  11.941 40.032 12.161 40.536 ;
     RECT  12.013 9.216 12.517 10.2 ;
     RECT  12.373 39.792 12.517 39.816 ;
     RECT  12.517 9.216 12.589 10.248 ;
     RECT  12.035 4.512 12.625 5.16 ;
     RECT  12.089 2.976 12.733 3.432 ;
     RECT  12.625 4.464 12.733 5.16 ;
     RECT  12.589 9.216 12.733 10.632 ;
     RECT  11.765 25.152 12.805 27.768 ;
     RECT  12.733 9.216 12.841 10.968 ;
     RECT  12.017 12 12.841 12.552 ;
     RECT  10.804 41.904 12.901 41.928 ;
     RECT  12.805 24.96 12.913 27.768 ;
     RECT  12.901 41.376 12.913 41.928 ;
     RECT  11.989 30.384 13.021 33.816 ;
     RECT  12.373 35.328 13.021 35.352 ;
     RECT  12.913 41.376 13.052 42.072 ;
     RECT  12.769 43.344 13.052 43.368 ;
     RECT  12.035 6.288 13.057 7.416 ;
     RECT  12.841 9.216 13.057 12.552 ;
     RECT  12.053 13.536 13.057 15.816 ;
     RECT  12.913 24.96 13.057 28.008 ;
     RECT  12.053 16.992 13.09 21.96 ;
     RECT  12.332 38.4 13.093 38.424 ;
     RECT  12.517 39.696 13.129 39.816 ;
     RECT  13.052 41.376 13.129 43.368 ;
     RECT  13.129 39.696 13.139 43.368 ;
     RECT  13.021 30.384 13.201 35.352 ;
     RECT  12.017 36.528 13.201 36.6 ;
     RECT  12.733 2.976 13.208 5.16 ;
     RECT  13.057 6.288 13.208 15.816 ;
     RECT  13.09 16.8 13.208 21.96 ;
     RECT  13.093 23.136 13.208 23.16 ;
     RECT  13.057 24.432 13.208 28.008 ;
     RECT  12.949 29.088 13.208 29.112 ;
     RECT  13.201 30.384 13.208 36.6 ;
     RECT  13.093 37.68 13.208 38.424 ;
     RECT  13.139 39.696 13.208 42.264 ;
     RECT  13.208 2.148 13.235 42.264 ;
     RECT  13.235 2.148 13.312 42.216 ;
     RECT  13.139 43.296 13.381 43.368 ;
     RECT  13.312 2.304 13.504 42.216 ;
     RECT  13.504 11.136 13.709 15.816 ;
     RECT  13.504 16.8 13.709 37.272 ;
     RECT  13.709 17.088 13.781 37.272 ;
     RECT  13.504 38.736 13.811 42.216 ;
     RECT  13.381 43.296 13.853 44.184 ;
     RECT  13.709 11.136 13.997 11.16 ;
     RECT  13.709 12.192 14.069 15.816 ;
     RECT  13.811 38.736 14.077 41.928 ;
     RECT  13.504 2.304 14.393 2.52 ;
     RECT  13.781 26.784 14.393 37.272 ;
     RECT  14.077 38.736 14.429 40.632 ;
     RECT  13.853 44.16 14.537 44.184 ;
     RECT  14.069 15.792 14.785 15.816 ;
     RECT  14.393 26.784 14.789 30.408 ;
     RECT  14.393 31.392 14.825 37.272 ;
     RECT  14.069 12.192 14.861 14.712 ;
     RECT  14.077 41.664 14.867 41.928 ;
     RECT  14.785 15.792 14.893 16.008 ;
     RECT  13.781 17.088 14.893 25.704 ;
     RECT  13.504 7.968 14.897 10.152 ;
     RECT  14.429 40.56 14.905 40.632 ;
     RECT  14.393 2.496 15.037 2.52 ;
     RECT  14.893 15.792 15.289 25.704 ;
     RECT  14.789 26.784 15.289 26.808 ;
     RECT  14.429 38.736 15.397 39.384 ;
     RECT  15.037 2.496 15.433 2.904 ;
     RECT  15.433 2.496 15.541 3.48 ;
     RECT  13.504 4.464 15.541 6.84 ;
     RECT  14.897 7.968 15.541 9.384 ;
     RECT  14.861 12.288 15.577 14.712 ;
     RECT  15.289 15.792 15.577 26.808 ;
     RECT  14.789 27.792 15.577 30.408 ;
     RECT  14.825 31.392 15.577 37.128 ;
     RECT  15.541 10.848 15.649 10.872 ;
     RECT  15.577 12.288 15.757 26.808 ;
     RECT  15.577 27.792 15.757 37.128 ;
     RECT  15.397 38.208 15.793 39.384 ;
     RECT  14.905 40.56 15.793 40.584 ;
     RECT  15.649 10.848 15.829 11.256 ;
     RECT  15.757 12.288 15.829 37.128 ;
     RECT  15.541 2.496 15.908 9.384 ;
     RECT  15.829 10.848 15.908 37.128 ;
     RECT  15.793 38.208 15.908 40.584 ;
     RECT  14.867 41.904 15.908 41.928 ;
     RECT  15.908 2.148 16.012 42.132 ;
     RECT  16.012 2.418 16.204 41.928 ;
     RECT  16.204 4.128 16.265 7.368 ;
     RECT  16.204 8.448 16.409 26.328 ;
     RECT  16.409 8.448 16.595 23.352 ;
     RECT  16.409 24.48 16.697 26.328 ;
     RECT  16.265 4.128 16.913 7.224 ;
     RECT  16.697 24.624 16.913 26.328 ;
     RECT  16.204 27.696 16.913 37.128 ;
     RECT  16.913 28.944 16.921 37.128 ;
     RECT  16.913 24.624 17.057 24.84 ;
     RECT  16.595 14.208 17.129 23.352 ;
     RECT  17.057 24.624 17.129 24.744 ;
     RECT  16.913 6.288 17.201 7.224 ;
     RECT  16.913 26.208 17.228 26.328 ;
     RECT  16.913 27.696 17.228 27.72 ;
     RECT  17.228 26.208 17.273 27.72 ;
     RECT  17.273 26.736 17.315 27.72 ;
     RECT  16.595 8.448 17.417 13.128 ;
     RECT  17.201 6.288 17.453 6.84 ;
     RECT  17.129 15.936 17.489 23.352 ;
     RECT  16.913 4.128 17.521 5.016 ;
     RECT  17.315 27.696 17.597 27.72 ;
     RECT  17.521 3.984 17.629 5.016 ;
     RECT  17.417 10.176 17.701 13.128 ;
     RECT  17.489 23.28 17.845 23.352 ;
     RECT  17.129 24.624 17.845 24.648 ;
     RECT  16.204 38.112 18.133 40.2 ;
     RECT  16.204 41.376 18.133 41.928 ;
     RECT  17.701 10.176 18.169 13.176 ;
     RECT  17.129 14.208 18.169 14.712 ;
     RECT  16.921 28.944 18.169 30.408 ;
     RECT  16.921 31.488 18.169 37.128 ;
     RECT  18.133 38.112 18.169 41.928 ;
     RECT  17.845 23.28 18.349 24.648 ;
     RECT  18.169 28.944 18.349 41.928 ;
     RECT  17.417 8.448 18.565 9.096 ;
     RECT  18.169 10.176 18.565 14.712 ;
     RECT  17.489 15.936 18.565 22.296 ;
     RECT  18.349 23.28 18.565 25.56 ;
     RECT  17.629 3.408 18.608 5.016 ;
     RECT  17.453 6.288 18.608 6.648 ;
     RECT  18.565 8.448 18.608 14.712 ;
     RECT  18.565 15.936 18.608 25.56 ;
     RECT  18.349 27.984 18.608 41.928 ;
     RECT  18.608 2.148 18.712 42.132 ;
     RECT  18.712 2.418 18.904 41.862 ;
     RECT  18.904 27.072 18.965 41.592 ;
     RECT  18.965 27.072 19.187 38.76 ;
     RECT  18.904 4.848 19.289 5.016 ;
     RECT  18.965 40.416 19.433 41.592 ;
     RECT  18.904 6.288 19.505 6.696 ;
     RECT  19.187 27.072 19.541 27.096 ;
     RECT  18.904 2.832 19.613 3.336 ;
     RECT  18.904 8.976 19.763 14.616 ;
     RECT  18.904 16.08 19.897 23.304 ;
     RECT  18.904 7.728 19.933 7.992 ;
     RECT  19.763 8.976 19.933 14.232 ;
     RECT  19.187 28.272 19.933 38.76 ;
     RECT  19.897 15.36 20.045 23.304 ;
     RECT  19.613 3.312 20.117 3.336 ;
     RECT  20.045 15.456 20.149 23.304 ;
     RECT  18.904 24.624 20.149 26.04 ;
     RECT  20.149 15.456 20.293 26.04 ;
     RECT  19.505 6.624 20.473 6.696 ;
     RECT  19.433 40.896 20.545 41.592 ;
     RECT  19.933 7.728 20.761 14.232 ;
     RECT  20.473 6.192 20.78 6.696 ;
     RECT  20.761 7.68 20.78 14.232 ;
     RECT  19.933 28.272 20.905 39.384 ;
     RECT  19.289 4.848 21.085 4.872 ;
     RECT  20.78 6.192 21.193 14.232 ;
     RECT  21.085 4.848 21.308 4.968 ;
     RECT  21.193 6 21.308 14.232 ;
     RECT  20.293 15.456 21.308 26.808 ;
     RECT  20.905 28.272 21.308 39.912 ;
     RECT  20.545 40.896 21.308 41.64 ;
     RECT  21.308 2.148 21.412 42.132 ;
     RECT  21.412 2.418 21.604 41.862 ;
     RECT  21.604 30.576 21.701 41.544 ;
     RECT  21.604 6.672 21.845 14.472 ;
     RECT  21.604 15.504 21.875 29.592 ;
     RECT  21.701 30.576 21.881 31.464 ;
     RECT  21.701 32.496 22.067 41.544 ;
     RECT  21.881 30.576 22.097 30.6 ;
     RECT  22.067 32.496 22.105 41.448 ;
     RECT  22.105 39.744 22.108 41.448 ;
     RECT  22.105 32.496 22.277 38.76 ;
     RECT  22.277 32.496 22.313 38.568 ;
     RECT  21.845 10.08 22.529 14.472 ;
     RECT  22.529 12.288 22.565 14.472 ;
     RECT  21.604 4.224 22.633 5.016 ;
     RECT  21.845 6.672 22.633 9.096 ;
     RECT  22.633 3.696 22.741 5.016 ;
     RECT  22.108 41.04 22.781 41.448 ;
     RECT  22.741 2.928 22.813 5.016 ;
     RECT  22.108 39.744 22.817 39.768 ;
     RECT  22.565 14.112 22.849 14.472 ;
     RECT  21.875 15.504 22.849 24.984 ;
     RECT  21.875 26.016 22.849 29.592 ;
     RECT  22.633 6.288 22.957 9.096 ;
     RECT  22.529 10.08 22.957 11.256 ;
     RECT  22.849 14.112 22.961 29.592 ;
     RECT  22.313 32.496 22.961 35.352 ;
     RECT  22.813 2.784 22.993 5.016 ;
     RECT  22.781 41.04 22.997 41.352 ;
     RECT  22.997 41.04 23.033 41.256 ;
     RECT  22.313 36.72 23.269 38.568 ;
     RECT  22.993 2.784 23.281 5.16 ;
     RECT  23.137 30.624 23.324 30.648 ;
     RECT  23.269 36.72 23.353 39.528 ;
     RECT  23.281 2.784 23.425 5.256 ;
     RECT  22.957 6.288 23.425 11.256 ;
     RECT  22.565 12.288 23.713 13.08 ;
     RECT  22.961 14.112 23.713 23.352 ;
     RECT  23.425 2.784 23.749 11.256 ;
     RECT  23.713 12.288 23.749 23.352 ;
     RECT  23.353 36.384 23.749 39.528 ;
     RECT  22.961 24.48 23.785 29.592 ;
     RECT  23.324 30.624 23.785 31.128 ;
     RECT  23.749 36.096 23.929 39.528 ;
     RECT  23.033 41.04 23.929 41.064 ;
     RECT  23.749 2.784 24.008 23.352 ;
     RECT  23.785 24.48 24.008 31.128 ;
     RECT  22.961 32.496 24.008 34.92 ;
     RECT  23.929 36.096 24.008 41.064 ;
     RECT  24.008 2.148 24.112 42.132 ;
     RECT  24.112 2.418 24.304 41.862 ;
     RECT  24.304 2.784 24.365 23.304 ;
     RECT  24.304 31.584 24.46 40.056 ;
     RECT  24.365 10.608 24.581 23.304 ;
     RECT  24.581 10.992 24.617 23.304 ;
     RECT  24.617 11.136 24.653 23.304 ;
     RECT  24.365 2.784 24.659 9.624 ;
     RECT  24.659 2.784 24.681 3.576 ;
     RECT  24.46 31.68 25.013 40.056 ;
     RECT  24.653 11.232 25.121 23.304 ;
     RECT  24.659 4.608 25.477 9.624 ;
     RECT  24.304 24.624 25.549 29.928 ;
     RECT  24.681 3.36 25.621 3.576 ;
     RECT  25.477 4.608 25.621 9.96 ;
     RECT  25.121 11.232 25.621 23.112 ;
     RECT  25.549 24.624 25.676 30.12 ;
     RECT  24.304 41.328 25.729 41.64 ;
     RECT  25.621 3.36 25.733 23.112 ;
     RECT  25.676 24.624 26.089 30.648 ;
     RECT  25.013 31.68 26.089 39.912 ;
     RECT  25.733 10.56 26.197 23.112 ;
     RECT  26.089 24.624 26.197 39.912 ;
     RECT  25.729 40.944 26.449 41.64 ;
     RECT  25.733 3.36 26.708 9.528 ;
     RECT  26.197 10.56 26.708 39.912 ;
     RECT  26.449 40.944 26.708 41.688 ;
     RECT  26.708 2.148 26.812 42.132 ;
     RECT  26.812 2.418 27.004 41.862 ;
     RECT  27.004 31.872 27.155 31.896 ;
     RECT  27.004 10.32 27.203 26.04 ;
     RECT  27.004 36.528 27.251 38.712 ;
     RECT  27.203 10.32 27.317 25.512 ;
     RECT  27.251 36.528 27.317 38.52 ;
     RECT  27.317 14.736 27.497 25.512 ;
     RECT  27.004 27.648 27.497 30.888 ;
     RECT  27.497 27.648 27.641 30.84 ;
     RECT  27.004 41.616 27.713 41.688 ;
     RECT  27.004 3.36 27.821 4.536 ;
     RECT  27.317 10.32 27.965 13.704 ;
     RECT  27.004 40.32 27.997 40.44 ;
     RECT  27.713 41.616 27.997 41.64 ;
     RECT  27.641 27.648 28.073 27.864 ;
     RECT  27.004 33.024 28.249 35.544 ;
     RECT  27.641 29.28 28.253 30.84 ;
     RECT  28.249 33.024 28.321 35.784 ;
     RECT  28.321 33.024 28.357 35.832 ;
     RECT  27.317 37.104 28.357 38.52 ;
     RECT  28.357 33.024 28.397 38.808 ;
     RECT  27.004 8.736 28.429 8.856 ;
     RECT  27.965 10.32 28.429 11.256 ;
     RECT  27.497 16.128 28.453 25.512 ;
     RECT  28.397 34.992 28.453 38.808 ;
     RECT  28.393 31.872 28.465 31.896 ;
     RECT  28.397 33.024 28.465 33.672 ;
     RECT  28.453 16.128 28.501 26.28 ;
     RECT  28.253 29.328 28.573 30.84 ;
     RECT  28.465 31.872 28.573 33.672 ;
     RECT  27.965 12.288 28.604 13.704 ;
     RECT  27.497 14.88 28.604 14.904 ;
     RECT  28.453 34.992 28.645 39.048 ;
     RECT  27.997 40.32 28.645 41.64 ;
     RECT  27.821 3.888 28.897 4.536 ;
     RECT  27.004 5.712 28.897 7.752 ;
     RECT  28.645 34.992 28.933 41.64 ;
     RECT  28.249 2.832 28.969 2.856 ;
     RECT  28.897 3.888 28.969 7.752 ;
     RECT  28.604 12.288 29.005 14.904 ;
     RECT  28.501 15.936 29.005 26.28 ;
     RECT  28.969 2.832 29.408 7.752 ;
     RECT  28.429 8.736 29.408 11.256 ;
     RECT  29.005 12.288 29.408 26.28 ;
     RECT  28.073 27.84 29.408 27.864 ;
     RECT  28.573 29.328 29.408 33.672 ;
     RECT  28.933 34.992 29.408 41.688 ;
     RECT  29.408 2.148 29.512 42.132 ;
     RECT  29.512 2.352 29.704 41.862 ;
     RECT  29.704 39.84 29.765 41.688 ;
     RECT  29.704 29.568 29.801 37.176 ;
     RECT  29.801 29.568 29.843 32.472 ;
     RECT  29.765 39.84 29.939 41.064 ;
     RECT  29.939 39.84 29.981 40.44 ;
     RECT  29.704 21.456 30.017 27.336 ;
     RECT  29.843 29.952 30.227 32.472 ;
     RECT  29.704 2.352 30.305 11.256 ;
     RECT  30.227 29.952 30.305 30.744 ;
     RECT  30.305 2.352 30.377 9.864 ;
     RECT  30.377 2.88 30.457 9.864 ;
     RECT  30.457 3.936 30.557 9.864 ;
     RECT  30.305 30.72 30.665 30.744 ;
     RECT  29.704 12.816 30.689 20.472 ;
     RECT  30.017 21.456 30.689 22.776 ;
     RECT  30.017 23.856 30.697 27.336 ;
     RECT  30.457 2.88 30.701 2.904 ;
     RECT  30.689 12.816 30.709 22.776 ;
     RECT  30.709 12.288 30.737 22.776 ;
     RECT  29.981 39.936 30.737 40.44 ;
     RECT  30.697 23.856 30.773 27.48 ;
     RECT  29.801 33.6 30.809 37.176 ;
     RECT  30.227 31.92 30.851 32.472 ;
     RECT  30.809 33.84 30.877 37.176 ;
     RECT  30.557 3.936 30.917 9.672 ;
     RECT  30.737 12.288 30.989 22.296 ;
     RECT  30.305 10.992 30.995 11.256 ;
     RECT  30.989 12.288 31.061 19.08 ;
     RECT  30.773 26.208 31.129 27.48 ;
     RECT  30.877 33.84 31.129 37.368 ;
     RECT  30.773 23.856 31.196 24.888 ;
     RECT  30.995 11.136 31.237 11.256 ;
     RECT  31.061 12.288 31.237 14.232 ;
     RECT  30.851 31.92 31.309 31.944 ;
     RECT  30.917 3.936 31.561 4.248 ;
     RECT  31.129 33.84 31.561 37.608 ;
     RECT  31.525 38.688 31.561 38.712 ;
     RECT  31.129 26.208 31.633 27.672 ;
     RECT  31.021 29.664 31.669 29.688 ;
     RECT  30.989 20.352 31.777 22.296 ;
     RECT  31.196 23.52 31.777 24.888 ;
     RECT  30.737 39.936 31.777 40.2 ;
     RECT  31.777 20.352 31.885 24.888 ;
     RECT  31.237 11.136 31.957 14.232 ;
     RECT  31.061 15.504 31.957 19.08 ;
     RECT  31.885 20.352 31.957 25.224 ;
     RECT  31.669 29.664 31.957 29.784 ;
     RECT  31.561 33.84 31.957 38.712 ;
     RECT  31.777 39.888 31.957 40.2 ;
     RECT  31.561 3.312 32.108 4.248 ;
     RECT  30.917 5.28 32.108 9.672 ;
     RECT  31.957 10.704 32.108 14.232 ;
     RECT  31.957 15.504 32.108 25.224 ;
     RECT  31.633 26.208 32.108 27.96 ;
     RECT  31.957 29.664 32.108 30.024 ;
     RECT  31.309 31.104 32.108 31.944 ;
     RECT  31.957 33.84 32.108 40.2 ;
     RECT  30.805 41.568 32.108 41.592 ;
     RECT  32.108 2.148 32.212 42.132 ;
     RECT  32.212 2.418 32.404 41.862 ;
     RECT  32.404 3.312 32.429 4.248 ;
     RECT  32.404 29.76 32.465 31.128 ;
     RECT  32.404 32.832 32.753 39.768 ;
     RECT  32.753 33.024 32.789 39.768 ;
     RECT  32.404 12.288 32.933 25.128 ;
     RECT  32.429 3.36 33.365 4.248 ;
     RECT  32.404 5.328 33.443 9.624 ;
     RECT  32.465 30.048 33.577 31.128 ;
     RECT  33.577 29.52 33.685 31.128 ;
     RECT  32.933 24.192 33.721 25.128 ;
     RECT  32.404 26.64 33.721 27.96 ;
     RECT  32.404 41.04 33.721 41.064 ;
     RECT  33.443 6 33.761 9.624 ;
     RECT  33.721 24.192 33.793 27.96 ;
     RECT  33.721 41.04 33.797 41.784 ;
     RECT  33.365 3.36 33.901 3.912 ;
     RECT  33.685 29.52 33.973 31.944 ;
     RECT  32.789 33.312 33.973 39.576 ;
     RECT  32.404 10.848 34.153 11.304 ;
     RECT  33.973 29.52 34.189 39.576 ;
     RECT  34.117 40.56 34.189 40.584 ;
     RECT  32.933 12.288 34.369 23.16 ;
     RECT  33.793 24.192 34.369 28.44 ;
     RECT  33.901 2.88 34.621 3.912 ;
     RECT  33.761 8.832 34.729 9.624 ;
     RECT  34.153 10.656 34.729 11.304 ;
     RECT  33.761 6 34.801 7.8 ;
     RECT  34.729 8.832 34.801 11.304 ;
     RECT  34.621 2.88 34.808 4.68 ;
     RECT  34.801 6 34.808 11.304 ;
     RECT  34.369 12.288 34.808 28.44 ;
     RECT  34.189 29.52 34.808 40.584 ;
     RECT  33.797 41.76 34.808 41.784 ;
     RECT  34.808 2.148 34.912 42.132 ;
     RECT  34.912 2.256 35.104 41.862 ;
     RECT  35.104 3.888 35.165 41.784 ;
     RECT  35.165 3.936 35.219 41.784 ;
     RECT  35.219 14.4 35.381 41.784 ;
     RECT  35.381 14.4 35.417 39.768 ;
     RECT  35.417 14.736 35.453 29.784 ;
     RECT  35.453 27.888 35.597 29.784 ;
     RECT  35.453 14.736 35.705 26.808 ;
     RECT  35.219 8.832 35.741 13.176 ;
     RECT  35.417 30.912 35.795 39.768 ;
     RECT  35.219 5.808 35.885 7.752 ;
     RECT  35.104 2.256 35.921 2.904 ;
     RECT  35.921 2.256 35.957 2.28 ;
     RECT  35.705 14.736 36.029 23.16 ;
     RECT  35.795 32.304 36.131 39.768 ;
     RECT  36.131 32.496 36.172 39.768 ;
     RECT  35.795 30.912 36.173 31.176 ;
     RECT  35.597 27.888 36.268 29.112 ;
     RECT  35.741 8.832 36.281 10.344 ;
     RECT  36.172 33.744 36.317 39.768 ;
     RECT  35.741 11.568 36.425 13.176 ;
     RECT  35.219 3.936 36.457 4.68 ;
     RECT  36.457 3.936 36.529 4.872 ;
     RECT  36.173 30.912 36.565 30.936 ;
     RECT  36.029 14.736 36.853 23.112 ;
     RECT  36.425 12 36.961 13.176 ;
     RECT  36.853 14.4 36.961 23.112 ;
     RECT  36.529 3.408 36.997 4.872 ;
     RECT  35.885 6.192 36.997 7.752 ;
     RECT  36.268 28.464 36.997 29.112 ;
     RECT  36.565 30.336 36.997 30.936 ;
     RECT  36.317 39.696 36.997 39.768 ;
     RECT  36.997 39.696 37.045 39.864 ;
     RECT  35.381 40.896 37.045 41.016 ;
     RECT  35.705 24.192 37.105 26.808 ;
     RECT  36.172 32.496 37.105 32.568 ;
     RECT  36.997 3.408 37.141 7.752 ;
     RECT  36.281 8.832 37.141 9.624 ;
     RECT  37.105 24.192 37.249 26.856 ;
     RECT  36.997 28.464 37.249 30.936 ;
     RECT  37.105 32.256 37.249 32.568 ;
     RECT  37.045 40.896 37.285 41.256 ;
     RECT  37.141 3.408 37.321 9.624 ;
     RECT  37.249 24.192 37.381 27.384 ;
     RECT  37.249 28.464 37.381 32.568 ;
     RECT  36.961 12 37.501 23.112 ;
     RECT  37.321 2.784 37.508 9.624 ;
     RECT  37.501 11.184 37.508 23.112 ;
     RECT  37.381 24.192 37.508 32.568 ;
     RECT  36.317 33.744 37.508 38.712 ;
     RECT  37.045 39.696 37.508 39.912 ;
     RECT  37.285 40.896 37.508 41.928 ;
     RECT  37.508 2.148 37.612 42.132 ;
     RECT  37.612 2.418 37.804 41.928 ;
     RECT  37.804 27.36 37.901 39.864 ;
     RECT  37.804 2.418 37.937 24.696 ;
     RECT  37.901 27.36 37.973 39.816 ;
     RECT  37.973 38.784 38.225 39.816 ;
     RECT  37.937 2.418 38.297 24.648 ;
     RECT  38.297 3.408 38.339 24.648 ;
     RECT  38.339 3.408 38.477 14.376 ;
     RECT  38.339 15.36 38.585 24.648 ;
     RECT  38.477 4.224 38.621 14.376 ;
     RECT  38.225 38.928 38.765 39.816 ;
     RECT  37.804 41.232 38.797 41.928 ;
     RECT  38.621 5.184 38.86 14.376 ;
     RECT  38.765 38.928 38.981 39.768 ;
     RECT  38.86 5.184 39.017 14.232 ;
     RECT  39.017 5.184 39.233 5.208 ;
     RECT  37.973 27.36 39.233 37.656 ;
     RECT  39.229 26.256 39.409 26.28 ;
     RECT  39.409 26.256 39.517 26.376 ;
     RECT  39.233 27.36 39.517 30.936 ;
     RECT  39.517 26.256 39.589 30.936 ;
     RECT  38.585 15.936 39.733 24.648 ;
     RECT  39.589 25.632 39.733 30.936 ;
     RECT  39.233 31.968 39.877 37.656 ;
     RECT  38.981 38.928 39.877 39.096 ;
     RECT  39.017 6.24 39.985 14.232 ;
     RECT  39.733 15.936 40.021 30.936 ;
     RECT  38.617 2.256 40.208 2.28 ;
     RECT  39.985 5.856 40.208 14.232 ;
     RECT  40.021 15.216 40.208 30.936 ;
     RECT  39.877 31.968 40.208 39.096 ;
     RECT  38.797 40.944 40.208 41.928 ;
     RECT  40.208 2.148 40.312 42.132 ;
     RECT  40.312 2.418 40.504 41.862 ;
     RECT  40.504 8.832 40.529 10.968 ;
     RECT  40.504 32.208 40.529 36.264 ;
     RECT  40.504 37.968 40.601 39.096 ;
     RECT  40.504 41.232 40.637 41.544 ;
     RECT  40.529 8.832 40.643 10.872 ;
     RECT  40.643 8.832 40.745 10.728 ;
     RECT  40.529 32.208 40.745 35.208 ;
     RECT  40.504 12.528 40.781 13.176 ;
     RECT  40.601 38.256 40.781 39.096 ;
     RECT  40.745 8.832 40.817 10.104 ;
     RECT  40.504 27.36 40.817 30.168 ;
     RECT  40.504 5.616 40.883 5.88 ;
     RECT  40.504 6.864 40.897 7.752 ;
     RECT  40.883 5.616 40.925 5.64 ;
     RECT  40.504 40.128 40.931 40.152 ;
     RECT  40.637 41.52 40.931 41.544 ;
     RECT  40.817 28.176 40.961 30.168 ;
     RECT  40.781 13.104 40.997 13.176 ;
     RECT  40.817 8.832 41.033 9.576 ;
     RECT  40.504 16.176 41.033 23.64 ;
     RECT  40.961 28.176 41.033 29.112 ;
     RECT  40.781 38.64 41.033 39.096 ;
     RECT  41.033 16.176 41.069 23.256 ;
     RECT  40.504 24.912 41.069 24.984 ;
     RECT  40.504 26.064 41.069 26.28 ;
     RECT  40.961 30.144 41.069 30.168 ;
     RECT  40.529 36.24 41.069 36.264 ;
     RECT  41.033 39.072 41.069 39.096 ;
     RECT  41.033 8.832 41.177 9.288 ;
     RECT  41.069 16.176 41.285 19.272 ;
     RECT  41.069 24.96 41.465 24.984 ;
     RECT  41.069 26.064 41.497 26.088 ;
     RECT  41.497 25.488 41.507 26.088 ;
     RECT  41.033 28.176 41.507 28.2 ;
     RECT  40.997 13.152 41.645 13.176 ;
     RECT  41.507 25.488 41.645 25.512 ;
     RECT  40.745 32.256 41.645 35.208 ;
     RECT  41.069 20.4 42.145 22.344 ;
     RECT  42.145 20.304 42.577 22.344 ;
     RECT  40.897 7.056 42.757 7.752 ;
     RECT  42.757 6.96 43.333 7.752 ;
     RECT  41.285 16.176 43.333 19.08 ;
     RECT  42.577 20.304 43.333 22.92 ;
     RECT  43.333 6.864 43.405 7.752 ;
     RECT  41.177 8.832 43.409 8.856 ;
     RECT  41.645 32.496 44.089 35.208 ;
     RECT  44.089 32.4 44.125 35.208 ;
     RECT  43.333 16.176 44.161 22.92 ;
     RECT  43.405 6.864 44.196 6.888 ;
     RECT  43.405 6.888 44.22 6.96 ;
     RECT  43.405 6.96 44.196 6.984 ;
     RECT  43.405 6.984 44.22 7.056 ;
     RECT  43.405 7.056 44.196 7.08 ;
     RECT  43.405 7.08 44.22 7.152 ;
     RECT  43.405 7.152 44.196 7.176 ;
     RECT  43.405 7.176 44.22 7.248 ;
     RECT  43.405 7.248 44.196 7.272 ;
     RECT  43.405 7.272 44.22 7.344 ;
     RECT  43.405 7.344 44.196 7.368 ;
     RECT  43.405 7.368 44.22 7.44 ;
     RECT  43.405 7.44 44.196 7.464 ;
     RECT  43.405 7.464 44.22 7.536 ;
     RECT  43.405 7.536 44.196 7.56 ;
     RECT  43.405 7.56 44.22 7.632 ;
     RECT  43.405 7.632 44.196 7.656 ;
     RECT  43.405 7.656 44.22 7.728 ;
     RECT  43.405 7.728 44.196 7.752 ;
     RECT  43.405 7.752 44.22 7.824 ;
     RECT  43.405 7.824 44.196 7.848 ;
     RECT  44.161 15.984 44.22 16.08 ;
     RECT  44.161 16.08 44.196 16.104 ;
     RECT  44.161 16.104 44.22 16.176 ;
     RECT  44.161 16.176 44.196 16.2 ;
     RECT  44.161 16.2 44.22 16.272 ;
     RECT  44.161 16.272 44.196 16.296 ;
     RECT  44.161 16.296 44.22 16.368 ;
     RECT  44.161 16.368 44.196 16.392 ;
     RECT  44.161 16.392 44.22 16.464 ;
     RECT  44.161 16.464 44.196 16.488 ;
     RECT  44.161 16.488 44.22 16.56 ;
     RECT  44.161 16.56 44.196 16.584 ;
     RECT  44.161 16.584 44.22 16.656 ;
     RECT  44.161 16.656 44.196 16.68 ;
     RECT  44.161 16.68 44.22 16.752 ;
     RECT  44.161 16.752 44.196 16.776 ;
     RECT  44.161 16.776 44.22 16.848 ;
     RECT  44.161 16.848 44.196 16.872 ;
     RECT  44.161 16.872 44.22 16.944 ;
     RECT  44.161 16.944 44.196 16.968 ;
     RECT  44.161 16.968 44.22 17.04 ;
     RECT  44.161 17.04 44.196 17.064 ;
     RECT  44.161 17.064 44.22 17.136 ;
     RECT  44.161 17.136 44.196 17.16 ;
     RECT  44.161 17.16 44.22 17.232 ;
     RECT  44.161 17.232 44.196 17.256 ;
     RECT  44.161 17.256 44.22 17.328 ;
     RECT  44.161 17.328 44.196 17.352 ;
     RECT  44.161 17.352 44.22 17.424 ;
     RECT  44.161 17.424 44.196 17.448 ;
     RECT  44.161 17.448 44.22 17.52 ;
     RECT  44.161 17.52 44.196 17.544 ;
     RECT  44.161 17.544 44.22 17.616 ;
     RECT  44.161 17.616 44.196 17.64 ;
     RECT  44.161 17.64 44.22 17.712 ;
     RECT  44.161 17.712 44.196 17.736 ;
     RECT  44.161 17.736 44.22 17.808 ;
     RECT  44.161 17.808 44.196 17.832 ;
     RECT  44.161 17.832 44.22 17.904 ;
     RECT  44.161 17.904 44.196 17.928 ;
     RECT  44.161 17.928 44.22 18 ;
     RECT  44.161 18 44.196 18.024 ;
     RECT  44.161 18.024 44.22 18.096 ;
     RECT  44.161 18.096 44.196 18.12 ;
     RECT  44.161 18.12 44.22 18.192 ;
     RECT  44.161 18.192 44.196 18.216 ;
     RECT  44.161 18.216 44.22 18.288 ;
     RECT  44.161 18.288 44.196 18.312 ;
     RECT  44.161 18.312 44.22 18.384 ;
     RECT  44.161 18.384 44.196 18.408 ;
     RECT  44.161 18.408 44.22 18.48 ;
     RECT  44.161 18.48 44.196 18.504 ;
     RECT  44.161 18.504 44.22 18.576 ;
     RECT  44.161 18.576 44.196 18.6 ;
     RECT  44.161 18.6 44.22 18.672 ;
     RECT  44.161 18.672 44.196 18.696 ;
     RECT  44.161 18.696 44.22 18.768 ;
     RECT  44.161 18.768 44.196 18.792 ;
     RECT  44.161 18.792 44.22 18.864 ;
     RECT  44.161 18.864 44.196 18.888 ;
     RECT  44.161 18.888 44.22 18.96 ;
     RECT  44.161 18.96 44.196 18.984 ;
     RECT  44.161 18.984 44.22 19.056 ;
     RECT  44.161 19.056 44.196 19.08 ;
     RECT  44.161 19.08 44.22 19.92 ;
     RECT  44.161 19.92 44.196 19.944 ;
     RECT  44.161 19.944 44.22 20.016 ;
     RECT  44.161 20.016 44.196 20.04 ;
     RECT  44.161 20.04 44.22 20.112 ;
     RECT  44.161 20.112 44.196 20.136 ;
     RECT  44.161 20.136 44.22 20.208 ;
     RECT  44.161 20.208 44.196 20.232 ;
     RECT  44.161 20.232 44.22 20.304 ;
     RECT  44.161 20.304 44.196 20.328 ;
     RECT  44.161 20.328 44.22 20.4 ;
     RECT  44.161 20.4 44.196 20.424 ;
     RECT  44.161 20.424 44.22 20.496 ;
     RECT  44.161 20.496 44.196 20.52 ;
     RECT  44.161 20.52 44.22 20.592 ;
     RECT  44.161 20.592 44.196 20.616 ;
     RECT  44.161 20.616 44.22 20.688 ;
     RECT  44.161 20.688 44.196 20.712 ;
     RECT  44.161 20.712 44.22 20.784 ;
     RECT  44.161 20.784 44.196 20.808 ;
     RECT  44.161 20.808 44.22 20.88 ;
     RECT  44.161 20.88 44.196 20.904 ;
     RECT  44.161 20.904 44.22 20.976 ;
     RECT  44.161 20.976 44.196 21 ;
     RECT  44.161 21 44.22 21.072 ;
     RECT  44.161 21.072 44.196 21.096 ;
     RECT  44.161 21.096 44.22 21.168 ;
     RECT  44.161 21.168 44.196 21.192 ;
     RECT  44.161 21.192 44.22 21.264 ;
     RECT  44.161 21.264 44.196 21.288 ;
     RECT  44.161 21.288 44.22 21.36 ;
     RECT  44.161 21.36 44.196 21.384 ;
     RECT  44.161 21.384 44.22 21.456 ;
     RECT  44.161 21.456 44.196 21.48 ;
     RECT  44.161 21.48 44.22 21.552 ;
     RECT  44.161 21.552 44.196 21.576 ;
     RECT  44.161 21.576 44.22 21.648 ;
     RECT  44.161 21.648 44.196 21.672 ;
     RECT  44.161 21.672 44.22 21.744 ;
     RECT  44.161 21.744 44.196 21.768 ;
     RECT  44.161 21.768 44.22 21.84 ;
     RECT  44.161 21.84 44.196 21.864 ;
     RECT  44.161 21.864 44.22 21.936 ;
     RECT  44.161 21.936 44.196 21.96 ;
     RECT  44.161 21.96 44.22 22.032 ;
     RECT  44.161 22.032 44.196 22.056 ;
     RECT  44.161 22.056 44.22 22.128 ;
     RECT  44.161 22.128 44.196 22.152 ;
     RECT  44.161 22.152 44.22 22.224 ;
     RECT  44.161 22.224 44.196 22.248 ;
     RECT  44.161 22.248 44.22 22.32 ;
     RECT  44.161 22.32 44.196 22.344 ;
     RECT  44.161 22.344 44.22 22.416 ;
     RECT  44.161 22.416 44.196 22.44 ;
     RECT  44.161 22.44 44.22 22.512 ;
     RECT  44.161 22.512 44.196 22.536 ;
     RECT  44.161 22.536 44.22 22.608 ;
     RECT  44.161 22.608 44.196 22.632 ;
     RECT  44.161 22.632 44.22 22.704 ;
     RECT  44.161 22.704 44.196 22.728 ;
     RECT  44.161 22.728 44.22 22.8 ;
     RECT  44.161 22.8 44.196 22.824 ;
     RECT  44.161 22.824 44.22 22.896 ;
     RECT  44.161 22.896 44.196 22.92 ;
     RECT  44.125 31.92 44.22 32.208 ;
     RECT  44.125 32.208 44.196 32.232 ;
     RECT  44.125 32.232 44.22 32.304 ;
     RECT  44.125 32.304 44.196 32.328 ;
     RECT  44.125 32.328 44.22 32.4 ;
     RECT  44.125 32.4 44.196 32.424 ;
     RECT  44.125 32.424 44.22 32.496 ;
     RECT  44.125 32.496 44.196 32.52 ;
     RECT  44.125 32.52 44.22 32.592 ;
     RECT  44.125 32.592 44.196 32.616 ;
     RECT  44.125 32.616 44.22 32.688 ;
     RECT  44.125 32.688 44.196 32.712 ;
     RECT  44.125 32.712 44.22 32.784 ;
     RECT  44.125 32.784 44.196 32.808 ;
     RECT  44.125 32.808 44.22 32.88 ;
     RECT  44.125 32.88 44.196 32.904 ;
     RECT  44.125 32.904 44.22 32.976 ;
     RECT  44.125 32.976 44.196 33 ;
     RECT  44.125 33 44.22 33.072 ;
     RECT  44.125 33.072 44.196 33.096 ;
     RECT  44.125 33.096 44.22 33.168 ;
     RECT  44.125 33.168 44.196 33.192 ;
     RECT  44.125 33.192 44.22 33.264 ;
     RECT  44.125 33.264 44.196 33.288 ;
     RECT  44.125 33.288 44.22 33.36 ;
     RECT  44.125 33.36 44.196 33.384 ;
     RECT  44.125 33.384 44.22 33.456 ;
     RECT  44.125 33.456 44.196 33.48 ;
     RECT  44.125 33.48 44.22 33.552 ;
     RECT  44.125 33.552 44.196 33.576 ;
     RECT  44.125 33.576 44.22 33.648 ;
     RECT  44.125 33.648 44.196 33.672 ;
     RECT  44.125 33.672 44.22 33.744 ;
     RECT  44.125 33.744 44.196 33.768 ;
     RECT  44.125 33.768 44.22 33.84 ;
     RECT  44.125 33.84 44.196 33.864 ;
     RECT  44.125 33.864 44.22 33.936 ;
     RECT  44.125 33.936 44.196 33.96 ;
     RECT  44.125 33.96 44.22 34.032 ;
     RECT  44.125 34.032 44.196 34.056 ;
     RECT  44.125 34.056 44.22 34.128 ;
     RECT  44.125 34.128 44.196 34.152 ;
     RECT  44.125 34.152 44.22 34.224 ;
     RECT  44.125 34.224 44.196 34.248 ;
     RECT  44.125 34.248 44.22 34.32 ;
     RECT  44.125 34.32 44.196 34.344 ;
     RECT  44.125 34.344 44.22 34.416 ;
     RECT  44.125 34.416 44.196 34.44 ;
     RECT  44.125 34.44 44.22 34.512 ;
     RECT  44.125 34.512 44.196 34.536 ;
     RECT  44.125 34.536 44.22 34.608 ;
     RECT  44.125 34.608 44.196 34.632 ;
     RECT  44.125 34.632 44.22 34.704 ;
     RECT  44.125 34.704 44.196 34.728 ;
     RECT  44.125 34.728 44.22 34.8 ;
     RECT  44.125 34.8 44.196 34.824 ;
     RECT  44.125 34.824 44.22 34.896 ;
     RECT  44.125 34.896 44.196 34.92 ;
     RECT  44.125 34.92 44.22 34.992 ;
     RECT  44.125 34.992 44.196 35.016 ;
     RECT  44.125 35.016 44.22 35.088 ;
     RECT  44.125 35.088 44.196 35.112 ;
     RECT  44.125 35.112 44.22 35.184 ;
     RECT  44.125 35.184 44.196 35.208 ;
     RECT  44.22 15.984 44.273 16.008 ;
     RECT  44.22 20.64 44.273 20.664 ;
     RECT  44.22 31.92 44.273 31.944 ;
    LAYER M5 ;
     RECT  2.4 2.137 2.52 2.151 ;
     RECT  5.1 2.137 5.22 2.151 ;
     RECT  7.8 2.137 7.92 2.151 ;
     RECT  10.5 2.137 10.62 2.151 ;
     RECT  13.2 2.137 13.32 2.151 ;
     RECT  15.9 2.137 16.02 2.151 ;
     RECT  18.6 2.137 18.72 2.151 ;
     RECT  21.3 2.137 21.42 2.151 ;
     RECT  24 2.137 24.12 2.151 ;
     RECT  26.7 2.137 26.82 2.151 ;
     RECT  29.4 2.137 29.52 2.151 ;
     RECT  32.1 2.137 32.22 2.151 ;
     RECT  34.8 2.137 34.92 2.151 ;
     RECT  37.5 2.137 37.62 2.151 ;
     RECT  40.2 2.137 40.32 2.151 ;
     RECT  5.1 2.151 5.412 2.245 ;
     RECT  4.128 2.245 5.412 2.629 ;
     RECT  24 2.151 24.312 2.773 ;
     RECT  4.128 2.629 5.784 3.157 ;
     RECT  29.4 2.151 29.712 3.397 ;
     RECT  4.128 3.157 6.216 3.875 ;
     RECT  29.4 3.397 30.408 3.925 ;
     RECT  24 2.773 24.648 4.163 ;
     RECT  15.9 2.151 16.212 4.501 ;
     RECT  28.464 3.925 30.408 4.547 ;
     RECT  29.4 4.547 30.408 4.643 ;
     RECT  10.5 2.151 10.812 4.741 ;
     RECT  10.368 4.741 10.812 4.837 ;
     RECT  21.3 2.151 21.612 4.837 ;
     RECT  34.8 2.151 35.112 4.837 ;
     RECT  37.5 2.151 37.812 5.077 ;
     RECT  10.368 4.837 11.448 5.125 ;
     RECT  4.368 3.875 6.216 5.171 ;
     RECT  9.36 2.821 9.384 5.459 ;
     RECT  40.2 2.151 40.512 5.605 ;
     RECT  24 4.163 24.504 5.941 ;
     RECT  34.8 4.837 35.208 5.989 ;
     RECT  33.408 5.317 33.432 6.035 ;
     RECT  34.656 5.989 35.208 6.035 ;
     RECT  24 5.941 25.224 6.085 ;
     RECT  29.4 4.643 30.072 6.133 ;
     RECT  24 6.085 25.704 6.229 ;
     RECT  26.7 2.151 27.012 6.229 ;
     RECT  34.656 6.035 35.112 6.229 ;
     RECT  10.368 5.125 12.024 6.323 ;
     RECT  14.688 5.605 14.712 6.323 ;
     RECT  5.1 5.171 6.216 6.467 ;
     RECT  2.4 2.151 2.712 6.805 ;
     RECT  5.1 6.467 6.12 6.805 ;
     RECT  13.2 2.151 13.512 6.805 ;
     RECT  15.9 4.501 16.536 6.805 ;
     RECT  21.168 4.837 21.612 6.805 ;
     RECT  29.4 6.133 30.552 6.805 ;
     RECT  29.4 6.805 31.128 6.899 ;
     RECT  40.2 5.605 40.872 6.899 ;
     RECT  2.4 6.805 2.808 7.139 ;
     RECT  10.368 6.323 11.448 7.189 ;
     RECT  15.9 6.805 16.824 7.235 ;
     RECT  21.12 6.805 21.612 7.381 ;
     RECT  29.4 6.899 30.12 7.381 ;
     RECT  4.32 6.805 6.12 7.429 ;
     RECT  34.128 6.229 35.112 7.765 ;
     RECT  33.648 7.765 35.112 7.811 ;
     RECT  29.28 7.381 30.12 7.909 ;
     RECT  31.104 6.899 31.128 7.909 ;
     RECT  34.8 7.811 35.112 7.957 ;
     RECT  4.32 7.429 6.504 8.003 ;
     RECT  9.744 7.189 11.448 8.003 ;
     RECT  10.032 8.003 11.4 8.195 ;
     RECT  29.28 7.909 31.128 8.435 ;
     RECT  20.832 7.381 21.612 8.531 ;
     RECT  29.28 8.435 30.216 8.579 ;
     RECT  37.152 5.077 37.812 8.579 ;
     RECT  33.648 7.811 33.672 8.723 ;
     RECT  10.032 8.195 11.112 8.867 ;
     RECT  2.4 7.139 2.712 8.869 ;
     RECT  18.6 2.151 18.912 8.965 ;
     RECT  29.28 8.579 30.12 9.107 ;
     RECT  15.9 7.235 16.536 9.157 ;
     RECT  15.552 9.157 16.536 9.203 ;
     RECT  37.344 8.579 37.812 9.301 ;
     RECT  4.512 8.003 6.504 9.443 ;
     RECT  24 6.229 27.012 9.491 ;
     RECT  10.368 8.867 11.112 9.541 ;
     RECT  37.344 9.301 39.048 9.587 ;
     RECT  7.8 2.151 8.112 9.589 ;
     RECT  10.368 9.541 11.256 9.637 ;
     RECT  2.4 8.869 2.808 9.779 ;
     RECT  29.28 9.107 29.832 9.779 ;
     RECT  21.12 8.531 21.612 9.827 ;
     RECT  34.8 7.957 35.208 9.827 ;
     RECT  37.344 9.587 38.76 10.067 ;
     RECT  21.3 9.827 21.612 10.069 ;
     RECT  40.2 6.899 40.512 10.069 ;
     RECT  13.2 6.805 13.608 10.213 ;
     RECT  15.552 9.203 16.212 10.213 ;
     RECT  24 9.491 24.456 10.213 ;
     RECT  5.1 9.443 6.504 10.307 ;
     RECT  7.8 9.589 9.048 10.307 ;
     RECT  29.4 9.779 29.832 10.355 ;
     RECT  32.1 2.151 32.412 10.693 ;
     RECT  15.552 10.213 17.16 10.883 ;
     RECT  40.2 10.069 40.632 10.883 ;
     RECT  15.9 10.883 17.16 10.979 ;
     RECT  23.472 10.213 24.456 11.123 ;
     RECT  5.1 10.307 6.024 11.125 ;
     RECT  37.344 10.067 38.616 11.125 ;
     RECT  18.6 8.965 19.416 11.171 ;
     RECT  7.8 10.307 8.232 11.221 ;
     RECT  30.96 10.981 30.984 11.221 ;
     RECT  25.776 9.491 27.012 11.317 ;
     RECT  34.8 9.827 35.112 11.365 ;
     RECT  7.68 11.221 8.232 11.459 ;
     RECT  21.3 10.069 22.44 11.605 ;
     RECT  4.944 11.125 6.024 11.651 ;
     RECT  21.168 11.605 22.44 11.893 ;
     RECT  25.68 11.317 27.012 11.941 ;
     RECT  30.72 11.221 30.984 11.941 ;
     RECT  31.968 10.693 32.412 11.941 ;
     RECT  37.344 11.125 38.712 11.941 ;
     RECT  10.368 9.637 11.448 12.035 ;
     RECT  13.104 10.213 13.608 12.083 ;
     RECT  7.68 11.459 8.112 12.371 ;
     RECT  23.472 11.123 24.312 12.373 ;
     RECT  25.68 11.941 27.912 12.373 ;
     RECT  21.12 11.893 22.44 12.421 ;
     RECT  37.344 11.941 38.808 12.469 ;
     RECT  40.2 10.883 40.512 12.469 ;
     RECT  7.8 12.371 8.112 12.517 ;
     RECT  30.72 11.941 32.412 12.517 ;
     RECT  15.9 10.979 16.536 12.563 ;
     RECT  21.072 12.421 22.44 12.757 ;
     RECT  23.472 12.373 27.912 12.757 ;
     RECT  34.8 11.365 35.256 12.853 ;
     RECT  21.072 12.757 27.912 13.043 ;
     RECT  18.6 11.171 18.912 13.045 ;
     RECT  21.3 13.043 27.912 13.045 ;
     RECT  29.4 10.355 29.712 13.045 ;
     RECT  21.3 13.045 29.712 13.091 ;
     RECT  30.72 12.517 33.144 13.091 ;
     RECT  10.5 12.035 11.448 13.093 ;
     RECT  30.72 13.091 32.412 13.139 ;
     RECT  15.9 12.563 16.344 13.621 ;
     RECT  24 13.091 29.712 13.715 ;
     RECT  24 13.715 27.012 13.859 ;
     RECT  21.3 13.091 22.536 13.907 ;
     RECT  28.656 13.715 29.712 14.099 ;
     RECT  24 13.859 25.704 14.147 ;
     RECT  18.6 13.045 19.752 14.627 ;
     RECT  13.2 12.083 13.608 14.773 ;
     RECT  29.4 14.099 29.712 14.773 ;
     RECT  30.72 13.139 30.984 14.773 ;
     RECT  34.8 12.853 35.352 15.013 ;
     RECT  5.1 11.651 6.024 15.203 ;
     RECT  12.672 14.773 13.608 15.251 ;
     RECT  34.608 15.013 35.352 15.253 ;
     RECT  24 14.147 25.464 15.301 ;
     RECT  26.7 13.859 27.012 15.301 ;
     RECT  37.344 12.469 40.512 15.443 ;
     RECT  7.8 12.517 8.424 15.445 ;
     RECT  34.608 15.253 35.928 15.829 ;
     RECT  10.5 13.093 11.544 15.877 ;
     RECT  18.6 14.627 18.912 15.925 ;
     RECT  29.4 14.773 30.984 15.925 ;
     RECT  34.608 15.829 36.168 15.925 ;
     RECT  34.608 15.925 36.216 16.019 ;
     RECT  24 15.301 27.012 16.021 ;
     RECT  15.9 13.621 16.584 16.069 ;
     RECT  17.616 15.925 18.912 16.069 ;
     RECT  24 16.021 27.192 16.069 ;
     RECT  28.848 15.925 30.984 16.069 ;
     RECT  32.1 13.139 32.412 16.069 ;
     RECT  37.344 15.443 37.944 16.307 ;
     RECT  15.9 16.069 18.912 16.405 ;
     RECT  15.9 16.405 19.416 16.453 ;
     RECT  21.3 13.907 21.612 16.501 ;
     RECT  5.1 15.203 5.976 16.595 ;
     RECT  15.312 16.453 19.416 16.595 ;
     RECT  34.8 16.019 36.216 16.643 ;
     RECT  18.432 16.595 19.416 16.789 ;
     RECT  36.144 16.643 36.216 16.835 ;
     RECT  10.272 15.877 11.544 16.837 ;
     RECT  13.2 15.251 13.608 16.981 ;
     RECT  24 16.069 27.288 17.029 ;
     RECT  28.608 16.069 32.412 17.029 ;
     RECT  18.432 16.789 20.328 17.123 ;
     RECT  15.312 16.595 17.112 17.171 ;
     RECT  24 17.029 32.412 17.171 ;
     RECT  18.48 17.123 20.328 17.459 ;
     RECT  2.4 9.779 2.712 17.461 ;
     RECT  39.216 15.443 40.512 17.461 ;
     RECT  24 17.171 27.912 17.509 ;
     RECT  38.784 17.461 40.512 17.603 ;
     RECT  10.224 16.837 11.544 17.605 ;
     RECT  13.056 16.981 13.608 17.605 ;
     RECT  33.6 16.501 33.624 17.605 ;
     RECT  34.8 16.643 35.112 17.605 ;
     RECT  29.4 17.171 32.412 17.651 ;
     RECT  18.48 17.459 19.416 18.133 ;
     RECT  2.304 17.461 2.712 18.229 ;
     RECT  10.224 17.605 13.656 18.275 ;
     RECT  23.472 17.509 27.912 18.275 ;
     RECT  15.312 17.171 17.016 18.373 ;
     RECT  2.016 18.229 2.712 18.419 ;
     RECT  32.1 17.651 32.412 18.517 ;
     RECT  7.8 15.445 8.568 18.565 ;
     RECT  33.6 17.605 35.112 18.709 ;
     RECT  36.144 16.835 36.168 18.709 ;
     RECT  40.2 17.603 40.512 18.709 ;
     RECT  18.24 18.133 19.416 18.757 ;
     RECT  18.24 18.757 19.896 18.805 ;
     RECT  21.3 16.501 22.2 18.805 ;
     RECT  14.88 18.373 17.016 18.851 ;
     RECT  18.24 18.805 22.2 18.851 ;
     RECT  33.6 18.709 36.168 18.851 ;
     RECT  37.344 16.307 37.812 18.851 ;
     RECT  37.392 18.851 37.812 19.189 ;
     RECT  38.784 17.603 38.808 19.189 ;
     RECT  33.6 18.851 33.624 19.235 ;
     RECT  10.224 18.275 13.512 19.331 ;
     RECT  32.1 18.517 32.52 19.331 ;
     RECT  14.88 18.851 16.212 19.427 ;
     RECT  23.904 18.275 27.912 19.427 ;
     RECT  10.224 19.331 11.544 19.573 ;
     RECT  37.392 19.189 38.808 19.811 ;
     RECT  18.24 18.851 21.612 19.813 ;
     RECT  23.904 19.427 27.288 19.907 ;
     RECT  13.104 19.331 13.512 19.909 ;
     RECT  5.1 16.595 5.784 20.003 ;
     RECT  37.392 19.811 38.664 20.003 ;
     RECT  6.912 18.565 8.568 20.101 ;
     RECT  9.648 19.573 11.544 20.101 ;
     RECT  6.912 20.101 11.544 20.147 ;
     RECT  13.104 19.909 13.656 20.197 ;
     RECT  0.144 20.101 0.168 20.291 ;
     RECT  37.5 20.003 38.664 20.291 ;
     RECT  24 19.907 27.288 20.485 ;
     RECT  29.4 17.651 31.128 20.485 ;
     RECT  32.1 19.331 32.412 20.485 ;
     RECT  6.912 20.147 9.144 20.579 ;
     RECT  18 19.813 21.612 20.579 ;
     RECT  34.8 18.851 36.168 20.579 ;
     RECT  15.6 19.427 16.212 20.581 ;
     RECT  6.912 20.579 8.112 20.627 ;
     RECT  40.08 18.709 40.512 20.723 ;
     RECT  24 20.485 27.96 21.107 ;
     RECT  18 20.579 19.128 21.155 ;
     RECT  15.6 20.581 16.44 21.205 ;
     RECT  26.112 21.107 27.96 21.299 ;
     RECT  18 21.155 19.032 21.347 ;
     RECT  13.104 20.197 13.752 21.445 ;
     RECT  40.2 20.723 40.512 21.637 ;
     RECT  20.64 20.579 21.612 21.683 ;
     RECT  9.12 20.579 9.144 21.731 ;
     RECT  5.1 20.003 5.412 22.021 ;
     RECT  4.464 22.021 5.412 22.453 ;
     RECT  2.4 18.419 2.712 22.741 ;
     RECT  24 21.107 24.552 22.741 ;
     RECT  34.8 20.579 35.304 22.787 ;
     RECT  10.224 20.147 11.544 22.789 ;
     RECT  15.6 21.205 16.536 22.835 ;
     RECT  18.48 21.347 19.032 22.835 ;
     RECT  4.464 22.453 5.544 23.027 ;
     RECT  15.6 22.835 16.212 23.123 ;
     RECT  20.688 21.683 21.612 23.317 ;
     RECT  26.112 21.299 27.192 23.317 ;
     RECT  40.2 21.637 40.776 23.363 ;
     RECT  37.5 20.291 38.232 23.651 ;
     RECT  15.9 23.123 16.212 23.893 ;
     RECT  34.8 22.787 35.112 23.893 ;
     RECT  9.696 22.789 11.544 23.939 ;
     RECT  18.48 22.835 18.912 24.035 ;
     RECT  26.112 23.317 27.96 24.085 ;
     RECT  29.4 20.485 32.412 24.085 ;
     RECT  26.112 24.085 32.412 24.131 ;
     RECT  15.9 23.893 16.344 24.469 ;
     RECT  24 22.741 25.128 24.469 ;
     RECT  13.104 21.445 13.848 24.949 ;
     RECT  7.8 20.627 8.112 25.045 ;
     RECT  9.696 23.939 11.448 25.139 ;
     RECT  23.376 24.469 25.128 25.139 ;
     RECT  10.32 25.139 11.448 25.187 ;
     RECT  28.464 24.131 32.412 25.619 ;
     RECT  2.4 22.741 3.432 25.621 ;
     RECT  4.656 23.027 5.544 25.621 ;
     RECT  15.9 24.469 16.68 25.667 ;
     RECT  34.8 23.893 35.352 25.669 ;
     RECT  7.44 25.045 8.112 25.715 ;
     RECT  28.464 25.619 30.216 25.715 ;
     RECT  2.4 25.621 5.544 25.763 ;
     RECT  2.4 25.763 5.412 25.859 ;
     RECT  26.112 24.131 27.192 25.861 ;
     RECT  25.44 25.861 27.192 26.051 ;
     RECT  37.5 23.651 37.812 26.053 ;
     RECT  40.2 23.363 40.512 26.053 ;
     RECT  25.44 26.051 27.012 26.243 ;
     RECT  40.2 26.053 41.496 26.245 ;
     RECT  10.32 25.187 10.812 26.437 ;
     RECT  15.9 25.667 16.44 26.725 ;
     RECT  40.08 26.245 41.496 26.771 ;
     RECT  20.688 23.317 21.912 26.819 ;
     RECT  23.376 25.139 24.312 26.819 ;
     RECT  34.8 25.669 36.12 26.819 ;
     RECT  34.8 26.819 35.208 26.915 ;
     RECT  18.6 24.035 18.912 27.061 ;
     RECT  21.3 26.819 21.912 27.061 ;
     RECT  7.68 25.715 8.112 27.301 ;
     RECT  25.44 26.243 25.464 27.301 ;
     RECT  37.392 26.053 37.812 27.349 ;
     RECT  15.9 26.725 17.304 27.731 ;
     RECT  2.4 25.859 2.712 27.781 ;
     RECT  3.984 25.859 5.412 27.781 ;
     RECT  28.464 25.715 29.832 27.875 ;
     RECT  9.84 26.437 10.812 27.877 ;
     RECT  2.4 27.781 5.412 27.923 ;
     RECT  37.392 27.349 38.856 28.067 ;
     RECT  40.2 26.771 41.496 28.211 ;
     RECT  12.816 24.949 13.848 28.261 ;
     RECT  7.296 27.301 8.376 28.357 ;
     RECT  25.392 27.301 25.464 28.403 ;
     RECT  26.592 26.243 27.012 28.453 ;
     RECT  36.192 27.877 36.216 28.453 ;
     RECT  37.392 28.067 38.184 28.453 ;
     RECT  9.648 27.877 10.812 28.547 ;
     RECT  21.3 27.061 22.2 28.547 ;
     RECT  6.768 28.357 8.376 28.595 ;
     RECT  26.592 28.453 27.144 28.835 ;
     RECT  21.3 28.547 21.612 28.885 ;
     RECT  23.472 26.819 24.312 28.885 ;
     RECT  15.9 27.731 16.44 28.933 ;
     RECT  25.44 28.403 25.464 28.979 ;
     RECT  34.8 26.915 35.112 29.029 ;
     RECT  36.192 28.453 38.184 29.029 ;
     RECT  18.6 27.061 19.176 29.077 ;
     RECT  7.296 28.595 8.376 29.123 ;
     RECT  34.8 29.029 38.184 29.123 ;
     RECT  4.656 27.923 5.412 29.221 ;
     RECT  15.9 28.933 16.872 29.365 ;
     RECT  23.376 28.885 24.312 29.509 ;
     RECT  26.7 28.835 27.144 29.555 ;
     RECT  15.696 29.365 16.872 29.605 ;
     RECT  20.4 28.885 21.612 29.605 ;
     RECT  12.816 28.261 13.944 29.651 ;
     RECT  28.608 27.875 29.832 29.699 ;
     RECT  4.656 29.221 5.736 29.747 ;
     RECT  7.68 29.123 8.376 29.891 ;
     RECT  29.4 29.699 29.832 29.941 ;
     RECT  26.7 29.555 27.012 30.085 ;
     RECT  2.4 27.923 3.432 30.181 ;
     RECT  4.656 29.747 5.412 30.181 ;
     RECT  12.816 29.651 13.848 30.373 ;
     RECT  15.696 29.605 17.256 30.419 ;
     RECT  18.24 29.077 19.176 30.469 ;
     RECT  20.16 29.605 21.612 30.469 ;
     RECT  18.24 30.469 21.612 30.563 ;
     RECT  2.4 30.181 5.412 30.659 ;
     RECT  2.4 30.659 3.24 30.851 ;
     RECT  10.368 28.547 10.812 30.851 ;
     RECT  34.8 29.123 37.812 30.947 ;
     RECT  29.4 29.941 30.216 30.949 ;
     RECT  23.376 29.509 24.408 31.139 ;
     RECT  4.656 30.659 5.412 31.379 ;
     RECT  15.696 30.419 16.872 31.477 ;
     RECT  15.408 31.477 16.872 31.523 ;
     RECT  10.5 30.851 10.812 31.525 ;
     RECT  12 30.373 13.848 31.525 ;
     RECT  10.5 31.525 13.848 31.571 ;
     RECT  20.976 30.563 21.612 31.619 ;
     RECT  24 31.139 24.408 31.619 ;
     RECT  18.24 30.563 19.56 31.669 ;
     RECT  0.144 31.429 0.168 31.715 ;
     RECT  15.408 31.523 16.212 31.811 ;
     RECT  7.68 29.891 8.232 31.813 ;
     RECT  25.728 30.085 27.012 31.861 ;
     RECT  29.04 30.949 30.216 31.955 ;
     RECT  7.2 31.813 8.232 32.195 ;
     RECT  40.2 28.211 41.016 32.291 ;
     RECT  34.8 30.947 35.784 32.293 ;
     RECT  37.008 30.947 37.812 32.293 ;
     RECT  17.184 31.669 19.56 32.437 ;
     RECT  31.248 25.619 32.412 32.437 ;
     RECT  34.08 32.293 37.812 32.437 ;
     RECT  38.784 31.285 38.808 32.437 ;
     RECT  15.9 31.811 16.212 32.821 ;
     RECT  17.184 32.437 19.8 32.821 ;
     RECT  12.72 31.571 13.848 32.965 ;
     RECT  15.9 32.821 19.8 33.011 ;
     RECT  30.816 32.437 32.412 33.013 ;
     RECT  34.08 32.437 38.808 33.013 ;
     RECT  22.704 32.581 22.728 33.059 ;
     RECT  10.5 31.571 11.448 33.107 ;
     RECT  25.728 31.861 27.144 33.155 ;
     RECT  40.2 32.291 40.512 33.253 ;
     RECT  18.24 33.011 19.8 33.299 ;
     RECT  29.04 31.955 29.832 33.349 ;
     RECT  18.24 33.299 18.912 33.395 ;
     RECT  22.896 33.253 22.92 33.589 ;
     RECT  24 31.619 24.312 33.589 ;
     RECT  40.2 33.253 41.112 33.589 ;
     RECT  34.08 33.013 39.096 33.683 ;
     RECT  34.8 33.683 39.096 33.779 ;
     RECT  30.816 33.013 32.76 33.875 ;
     RECT  21.12 31.619 21.612 34.117 ;
     RECT  22.896 33.589 24.312 34.117 ;
     RECT  7.2 32.195 8.112 34.165 ;
     RECT  25.728 33.155 27.012 34.259 ;
     RECT  6.48 34.165 8.112 34.693 ;
     RECT  28.416 33.349 29.832 34.741 ;
     RECT  30.816 33.875 32.412 34.741 ;
     RECT  37.008 33.779 38.184 34.741 ;
     RECT  15.9 33.011 17.208 34.787 ;
     RECT  15.9 34.787 17.016 34.883 ;
     RECT  21.12 34.117 24.312 34.931 ;
     RECT  4.8 31.379 5.412 35.077 ;
     RECT  6.48 34.693 8.472 35.077 ;
     RECT  40.08 33.589 41.112 35.171 ;
     RECT  25.44 34.501 25.464 35.315 ;
     RECT  12.528 32.965 13.848 35.317 ;
     RECT  34.8 33.779 35.4 35.317 ;
     RECT  37.008 34.741 38.232 35.317 ;
     RECT  4.8 35.077 8.472 35.363 ;
     RECT  7.2 35.363 8.472 35.699 ;
     RECT  28.416 34.741 32.412 35.747 ;
     RECT  15.9 34.883 16.584 35.749 ;
     RECT  24 34.931 24.312 35.797 ;
     RECT  34.8 35.317 38.232 35.939 ;
     RECT  18.288 33.395 18.912 36.037 ;
     RECT  40.08 35.171 40.512 36.229 ;
     RECT  36.192 35.939 37.812 36.419 ;
     RECT  28.416 35.747 30.84 36.515 ;
     RECT  26.7 34.259 27.012 36.661 ;
     RECT  21.12 34.931 22.92 36.755 ;
     RECT  39.36 36.229 40.512 36.901 ;
     RECT  15.792 35.749 16.584 36.997 ;
     RECT  18.24 36.037 18.912 36.997 ;
     RECT  32.1 35.747 32.412 36.997 ;
     RECT  4.8 35.363 5.544 37.043 ;
     RECT  10.5 33.107 10.812 37.045 ;
     RECT  12.384 35.317 13.848 37.045 ;
     RECT  21.12 36.755 22.056 37.139 ;
     RECT  24 35.797 25.224 37.477 ;
     RECT  28.416 36.515 30.504 37.523 ;
     RECT  23.28 37.477 25.224 37.573 ;
     RECT  36.48 36.419 37.812 37.619 ;
     RECT  23.28 37.573 25.704 37.667 ;
     RECT  34.8 35.939 35.112 38.149 ;
     RECT  31.968 36.997 32.412 38.195 ;
     RECT  15.792 36.997 18.912 38.243 ;
     RECT  25.536 37.667 25.704 38.243 ;
     RECT  25.68 38.243 25.704 38.387 ;
     RECT  9.984 37.045 13.848 38.675 ;
     RECT  33.984 38.149 35.112 38.677 ;
     RECT  26.7 36.661 27.24 38.723 ;
     RECT  12.48 38.675 13.848 38.725 ;
     RECT  39.312 36.901 40.512 38.725 ;
     RECT  20.064 38.149 20.088 38.771 ;
     RECT  28.368 37.573 28.392 38.771 ;
     RECT  29.4 37.523 30.504 38.773 ;
     RECT  21.168 37.139 22.056 38.819 ;
     RECT  39.312 38.725 40.92 38.963 ;
     RECT  12.48 38.725 14.04 39.061 ;
     RECT  15.9 38.243 18.912 39.251 ;
     RECT  33.984 38.677 35.208 39.251 ;
     RECT  7.2 35.699 8.112 39.253 ;
     RECT  23.28 37.667 24.312 39.301 ;
     RECT  26.7 38.723 27.012 39.301 ;
     RECT  32.1 38.195 32.412 39.301 ;
     RECT  3.696 36.997 3.72 39.445 ;
     RECT  5.1 37.043 5.412 39.445 ;
     RECT  15.9 39.251 16.968 39.539 ;
     RECT  18.24 39.251 18.912 39.539 ;
     RECT  23.28 39.301 24.888 39.539 ;
     RECT  12.48 39.061 14.856 39.827 ;
     RECT  6.816 39.253 8.112 39.877 ;
     RECT  21.168 38.819 21.612 39.877 ;
     RECT  26.208 39.301 27.012 39.923 ;
     RECT  37.056 37.619 37.812 39.923 ;
     RECT  28.464 38.773 30.504 39.971 ;
     RECT  21.072 39.877 21.612 40.165 ;
     RECT  31.968 39.301 32.412 40.165 ;
     RECT  34.8 39.251 35.208 40.547 ;
     RECT  37.2 39.923 37.812 40.933 ;
     RECT  3.696 39.445 5.412 40.979 ;
     RECT  3.696 40.979 3.72 41.075 ;
     RECT  6.816 39.877 8.568 41.075 ;
     RECT  12.816 39.827 14.856 41.075 ;
     RECT  28.464 39.971 29.928 41.075 ;
     RECT  37.056 40.933 37.812 41.267 ;
     RECT  12.816 41.075 13.848 41.411 ;
     RECT  21.072 40.165 22.056 41.555 ;
     RECT  40.2 38.963 40.92 41.555 ;
     RECT  31.536 40.165 32.412 41.603 ;
     RECT  21.072 41.555 21.612 41.651 ;
     RECT  24 39.539 24.888 41.651 ;
     RECT  14.832 41.075 14.856 41.699 ;
     RECT  7.8 41.075 8.568 41.891 ;
     RECT  2.4 30.851 2.712 42.129 ;
     RECT  5.1 40.979 5.412 42.129 ;
     RECT  7.8 41.891 8.112 42.129 ;
     RECT  10.5 38.675 10.812 42.129 ;
     RECT  15.9 39.539 16.212 42.129 ;
     RECT  18.6 39.539 18.912 42.129 ;
     RECT  21.3 41.651 21.612 42.129 ;
     RECT  24 41.651 24.312 42.129 ;
     RECT  26.7 39.923 27.012 42.129 ;
     RECT  29.4 41.075 29.712 42.129 ;
     RECT  32.1 41.603 32.412 42.129 ;
     RECT  34.8 40.547 35.112 42.129 ;
     RECT  37.5 41.267 37.812 42.129 ;
     RECT  40.2 41.555 40.512 42.129 ;
     RECT  2.4 42.129 2.52 42.143 ;
     RECT  5.1 42.129 5.22 42.143 ;
     RECT  7.8 42.129 7.92 42.143 ;
     RECT  10.5 42.129 10.62 42.143 ;
     RECT  15.9 42.129 16.02 42.143 ;
     RECT  18.6 42.129 18.72 42.143 ;
     RECT  21.3 42.129 21.42 42.143 ;
     RECT  24 42.129 24.12 42.143 ;
     RECT  26.7 42.129 26.82 42.143 ;
     RECT  29.4 42.129 29.52 42.143 ;
     RECT  32.1 42.129 32.22 42.143 ;
     RECT  34.8 42.129 34.92 42.143 ;
     RECT  37.5 42.129 37.62 42.143 ;
     RECT  40.2 42.129 40.32 42.143 ;
     RECT  12.816 41.411 13.8 44.196 ;
     RECT  12.84 44.196 12.912 44.24 ;
     RECT  12.936 44.196 13.008 44.24 ;
     RECT  13.032 44.196 13.104 44.24 ;
     RECT  13.128 44.196 13.2 44.24 ;
     RECT  13.224 44.196 13.296 44.24 ;
     RECT  13.32 44.196 13.392 44.24 ;
     RECT  13.416 44.196 13.488 44.24 ;
     RECT  13.512 44.196 13.584 44.24 ;
     RECT  13.608 44.196 13.68 44.24 ;
     RECT  13.704 44.196 13.776 44.24 ;
     RECT  2.712 2.245 4.128 3.875 ;
     RECT  8.112 2.821 9.36 5.459 ;
     RECT  9.384 2.821 10.5 4.741 ;
     RECT  27.012 3.925 28.464 4.547 ;
     RECT  30.072 4.643 30.408 6.133 ;
     RECT  9.384 4.741 10.368 5.459 ;
     RECT  12.024 5.125 13.2 6.323 ;
     RECT  32.412 5.317 33.408 6.035 ;
     RECT  33.432 5.317 34.8 5.989 ;
     RECT  13.512 5.605 14.688 6.323 ;
     RECT  14.712 5.605 15.9 6.323 ;
     RECT  25.224 5.941 26.7 6.085 ;
     RECT  33.432 5.989 34.656 6.035 ;
     RECT  34.128 6.035 34.656 6.229 ;
     RECT  25.704 6.085 26.7 6.229 ;
     RECT  13.512 6.323 13.608 6.805 ;
     RECT  6.12 6.467 6.216 7.429 ;
     RECT  2.808 6.805 4.32 7.139 ;
     RECT  31.128 6.805 32.1 8.435 ;
     RECT  30.12 6.899 31.104 7.909 ;
     RECT  6.504 7.429 7.8 10.307 ;
     RECT  32.412 7.765 33.648 8.723 ;
     RECT  33.672 7.811 34.8 8.723 ;
     RECT  11.112 8.195 11.4 9.541 ;
     RECT  10.032 8.867 10.368 9.589 ;
     RECT  16.212 9.203 16.536 10.213 ;
     RECT  39.048 9.301 40.2 9.587 ;
     RECT  24.456 9.491 25.776 11.123 ;
     RECT  11.256 9.541 11.4 9.637 ;
     RECT  38.76 9.587 40.2 10.067 ;
     RECT  9.048 9.589 10.368 10.307 ;
     RECT  38.616 10.067 40.2 11.125 ;
     RECT  17.16 10.213 18.6 10.979 ;
     RECT  22.44 10.213 23.472 12.757 ;
     RECT  7.68 10.307 7.8 11.221 ;
     RECT  29.712 10.355 29.832 10.981 ;
     RECT  29.712 10.981 30.96 11.221 ;
     RECT  30.984 10.981 31.968 11.941 ;
     RECT  24.312 11.123 25.776 11.317 ;
     RECT  38.712 11.125 40.2 11.941 ;
     RECT  29.712 11.221 30.72 14.773 ;
     RECT  24.312 11.317 25.68 12.373 ;
     RECT  8.112 11.459 8.232 12.517 ;
     RECT  27.912 11.941 29.4 13.045 ;
     RECT  38.808 11.941 40.2 12.469 ;
     RECT  16.344 12.563 16.536 13.621 ;
     RECT  22.536 13.091 24 13.907 ;
     RECT  30.984 13.139 32.1 16.069 ;
     RECT  25.704 13.859 26.7 14.147 ;
     RECT  25.464 14.147 26.7 15.301 ;
     RECT  11.544 14.773 12.672 15.251 ;
     RECT  35.928 15.253 37.344 15.829 ;
     RECT  37.944 15.443 39.216 16.307 ;
     RECT  36.168 15.829 37.344 15.925 ;
     RECT  16.584 15.925 17.616 16.069 ;
     RECT  36.216 15.925 37.344 16.835 ;
     RECT  34.608 16.019 34.8 16.501 ;
     RECT  27.288 16.069 28.608 17.029 ;
     RECT  37.812 16.307 39.216 17.461 ;
     RECT  32.412 16.501 33.6 18.517 ;
     RECT  33.624 16.501 34.8 17.605 ;
     RECT  17.112 16.595 18.432 17.123 ;
     RECT  35.112 16.643 36.144 18.709 ;
     RECT  20.328 16.789 21.3 17.459 ;
     RECT  36.168 16.835 37.344 18.851 ;
     RECT  11.544 16.981 13.056 17.605 ;
     RECT  17.112 17.123 18.48 17.171 ;
     RECT  17.016 17.171 18.48 18.133 ;
     RECT  27.912 17.171 29.4 19.427 ;
     RECT  19.416 17.459 21.3 18.757 ;
     RECT  37.812 17.461 38.784 19.189 ;
     RECT  22.2 17.509 23.472 18.275 ;
     RECT  38.808 17.603 40.2 18.709 ;
     RECT  31.128 17.651 32.1 20.485 ;
     RECT  17.016 18.133 18.24 18.851 ;
     RECT  13.512 18.275 13.656 18.373 ;
     RECT  13.512 18.373 14.88 19.427 ;
     RECT  32.52 18.517 33.6 19.235 ;
     RECT  5.784 18.565 6.912 20.003 ;
     RECT  38.808 18.709 40.08 19.811 ;
     RECT  19.896 18.757 21.3 18.805 ;
     RECT  18 18.851 18.24 19.813 ;
     RECT  33.624 18.851 34.8 19.235 ;
     RECT  36.168 18.851 37.392 20.003 ;
     RECT  13.512 19.427 13.752 19.909 ;
     RECT  27.288 19.427 29.4 20.485 ;
     RECT  8.568 19.573 9.648 20.101 ;
     RECT  38.664 19.811 40.08 20.291 ;
     RECT  13.656 19.909 13.752 20.197 ;
     RECT  5.412 20.003 6.912 20.627 ;
     RECT  36.168 20.003 37.5 20.579 ;
     RECT  9.144 20.147 10.224 21.731 ;
     RECT  27.96 20.485 29.4 21.299 ;
     RECT  8.112 20.579 9.12 21.731 ;
     RECT  19.128 20.579 20.64 21.155 ;
     RECT  16.536 21.205 18 21.347 ;
     RECT  9.696 21.731 10.224 22.789 ;
     RECT  3.432 22.741 4.464 23.027 ;
     RECT  25.128 22.741 26.112 25.139 ;
     RECT  35.112 22.787 35.304 23.893 ;
     RECT  16.212 22.835 16.344 23.893 ;
     RECT  3.432 23.027 4.656 25.621 ;
     RECT  27.96 23.317 29.4 24.085 ;
     RECT  11.448 23.939 11.544 24.949 ;
     RECT  27.192 24.131 28.464 26.051 ;
     RECT  21.912 24.469 23.376 26.819 ;
     RECT  11.448 24.949 12.816 25.187 ;
     RECT  9.84 25.139 10.32 26.437 ;
     RECT  24.312 25.139 26.112 25.861 ;
     RECT  30.216 25.619 31.248 25.715 ;
     RECT  16.44 25.667 16.68 26.725 ;
     RECT  36.12 25.669 37.5 26.053 ;
     RECT  29.832 25.715 31.248 29.941 ;
     RECT  2.712 25.859 3.984 27.781 ;
     RECT  24.312 25.861 25.44 27.301 ;
     RECT  27.012 26.051 28.464 27.875 ;
     RECT  36.12 26.053 37.392 26.819 ;
     RECT  25.464 26.243 26.592 28.835 ;
     RECT  17.304 26.725 18.6 27.731 ;
     RECT  40.08 26.771 40.2 27.349 ;
     RECT  21.912 26.819 23.472 27.061 ;
     RECT  35.208 26.819 37.392 26.915 ;
     RECT  35.112 26.915 37.392 27.877 ;
     RECT  22.2 27.061 23.472 28.547 ;
     RECT  8.376 27.301 9.84 27.877 ;
     RECT  24.312 27.301 25.392 28.403 ;
     RECT  38.856 27.349 40.2 28.067 ;
     RECT  16.44 27.731 18.6 28.933 ;
     RECT  27.012 27.875 28.608 28.453 ;
     RECT  8.376 27.877 9.648 28.547 ;
     RECT  35.112 27.877 36.192 29.029 ;
     RECT  36.216 27.877 37.392 28.453 ;
     RECT  3.432 27.923 4.656 30.181 ;
     RECT  5.412 28.357 6.768 28.595 ;
     RECT  24.312 28.403 25.44 28.979 ;
     RECT  27.144 28.453 28.608 29.555 ;
     RECT  23.376 28.547 23.472 28.885 ;
     RECT  5.412 28.595 5.736 29.221 ;
     RECT  25.464 28.835 26.7 28.979 ;
     RECT  19.176 28.885 20.4 29.605 ;
     RECT  16.872 28.933 18.6 29.077 ;
     RECT  24.312 28.979 26.7 29.509 ;
     RECT  16.872 29.077 18.24 29.605 ;
     RECT  24.408 29.509 26.7 30.085 ;
     RECT  17.256 29.605 18.24 30.419 ;
     RECT  19.176 29.605 20.16 30.469 ;
     RECT  29.04 29.699 29.4 30.949 ;
     RECT  30.216 29.941 31.248 31.955 ;
     RECT  24.408 30.085 25.728 31.619 ;
     RECT  10.812 30.373 12 31.525 ;
     RECT  16.872 30.419 18.24 31.523 ;
     RECT  19.56 30.563 20.976 31.619 ;
     RECT  3.24 30.659 4.656 30.851 ;
     RECT  35.784 30.947 37.008 32.293 ;
     RECT  23.376 31.139 24 32.581 ;
     RECT  37.812 31.285 38.784 32.437 ;
     RECT  38.808 31.285 40.2 33.013 ;
     RECT  16.212 31.523 18.24 31.669 ;
     RECT  11.448 31.571 12.72 32.965 ;
     RECT  19.56 31.619 21.12 32.437 ;
     RECT  24.312 31.619 25.728 34.259 ;
     RECT  16.212 31.669 17.184 32.821 ;
     RECT  29.832 31.955 31.248 32.437 ;
     RECT  40.512 32.291 41.016 33.253 ;
     RECT  19.8 32.437 21.12 33.299 ;
     RECT  29.832 32.437 30.816 34.741 ;
     RECT  21.612 32.581 22.704 33.059 ;
     RECT  22.728 32.581 24 33.059 ;
     RECT  11.448 32.965 12.528 33.107 ;
     RECT  17.208 33.011 18.24 33.395 ;
     RECT  32.76 33.013 34.08 33.683 ;
     RECT  39.096 33.013 40.2 33.589 ;
     RECT  21.612 33.059 24 33.253 ;
     RECT  27.012 33.155 27.144 33.349 ;
     RECT  21.612 33.253 22.896 34.117 ;
     RECT  22.92 33.253 24 33.589 ;
     RECT  27.012 33.349 28.416 36.661 ;
     RECT  17.208 33.395 18.288 34.787 ;
     RECT  39.096 33.589 40.08 33.779 ;
     RECT  38.184 33.779 38.232 34.741 ;
     RECT  5.412 34.165 6.48 35.077 ;
     RECT  24.312 34.259 26.7 34.501 ;
     RECT  24.312 34.501 25.44 35.315 ;
     RECT  25.464 34.501 26.7 35.315 ;
     RECT  17.016 34.787 18.288 34.883 ;
     RECT  18.24 34.883 18.288 36.037 ;
     RECT  22.92 34.931 24 36.755 ;
     RECT  24.312 35.315 26.7 35.797 ;
     RECT  30.84 35.747 32.1 36.515 ;
     RECT  25.224 35.797 26.7 37.573 ;
     RECT  35.112 35.939 36.192 36.419 ;
     RECT  37.812 35.939 38.232 36.229 ;
     RECT  37.812 36.229 39.36 36.901 ;
     RECT  35.112 36.419 36.48 37.619 ;
     RECT  30.504 36.515 32.1 36.997 ;
     RECT  27.24 36.661 28.416 37.523 ;
     RECT  22.056 36.755 24 37.477 ;
     RECT  37.812 36.901 39.312 38.963 ;
     RECT  2.712 36.997 3.696 41.075 ;
     RECT  3.72 36.997 4.8 37.043 ;
     RECT  30.504 36.997 31.968 38.195 ;
     RECT  3.72 37.043 5.1 39.445 ;
     RECT  21.12 37.139 21.168 38.149 ;
     RECT  22.056 37.477 23.28 38.819 ;
     RECT  27.24 37.523 29.4 37.573 ;
     RECT  25.704 37.573 26.7 38.387 ;
     RECT  27.24 37.573 28.368 38.723 ;
     RECT  28.392 37.573 29.4 38.771 ;
     RECT  35.112 37.619 35.208 38.677 ;
     RECT  24.312 37.667 25.536 38.243 ;
     RECT  18.912 38.149 20.064 38.771 ;
     RECT  20.088 38.149 21.168 38.771 ;
     RECT  30.504 38.195 32.1 39.301 ;
     RECT  15.792 38.243 15.9 39.061 ;
     RECT  24.312 38.243 25.68 38.387 ;
     RECT  24.312 38.387 26.7 39.301 ;
     RECT  27.012 38.723 28.368 38.771 ;
     RECT  21.072 38.771 21.168 39.877 ;
     RECT  27.012 38.771 29.4 38.773 ;
     RECT  27.012 38.773 28.464 41.075 ;
     RECT  21.612 38.819 23.28 39.539 ;
     RECT  14.856 39.061 15.9 41.699 ;
     RECT  16.968 39.251 18.24 39.539 ;
     RECT  5.412 39.253 6.816 41.075 ;
     RECT  24.888 39.301 26.208 39.923 ;
     RECT  30.504 39.301 31.968 39.971 ;
     RECT  21.612 39.539 22.056 40.165 ;
     RECT  37.056 39.923 37.2 40.933 ;
     RECT  31.536 39.971 31.968 40.165 ;
     RECT  3.72 40.979 5.1 41.075 ;
     RECT  13.848 41.075 14.832 41.411 ;
     RECT  13.8 41.411 14.832 41.699 ;
  END
END qfd_landh0d8_107_EW_44x44
END LIBRARY
